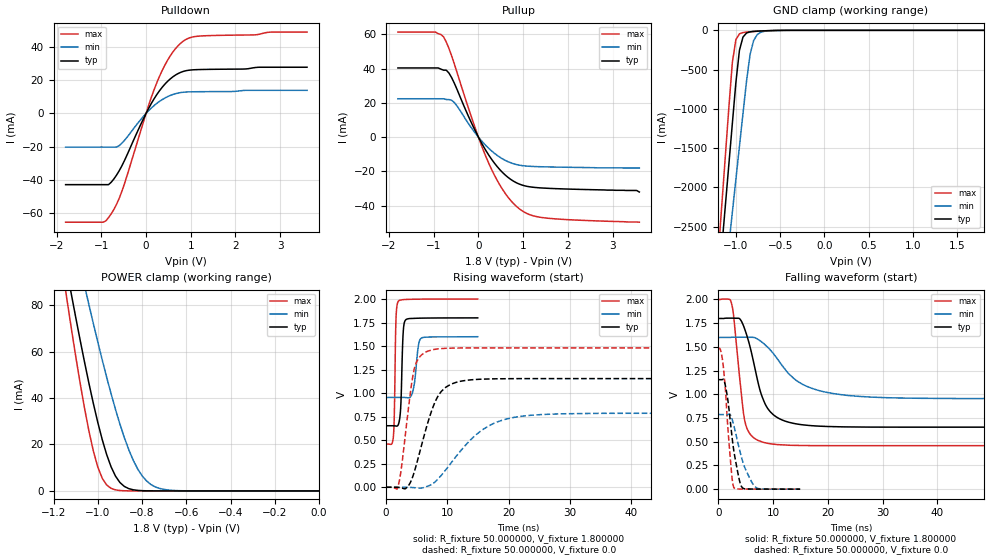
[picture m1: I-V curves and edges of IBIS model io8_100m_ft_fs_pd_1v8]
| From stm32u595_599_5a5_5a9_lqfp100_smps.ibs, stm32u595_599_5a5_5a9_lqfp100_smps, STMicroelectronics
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|   Model io8_100m_ft_fs_pd_1v8
[Model]  io8_100m_ft_fs_pd_1v8
Model_type I/O
Polarity   Non-Inverting
Enable   Active-Low
Vinl =   0.540000V
Vinh =   1.260000V
Vmeas =  0.900000V
Cref =   50.000000pF
Rref =   100.000000M
Vref =   0.0V
C_comp   3.148300pF   3.147400pF   3.196500pF
[Temperature Range]   25.000000   0.140000k   -40.000000
[Pullup Reference]   1.800000V   1.600000V   2.000000V
[Pulldown Reference]   0.0V   0.0V   0.0V
[POWER Clamp Reference]   1.800000V   1.600000V   2.000000V
[GND Clamp Reference]   0.0V   0.0V   0.0V
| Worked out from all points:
|   slope of the pulldown table from 0 to 0.27 V, typ, clamps not added: 21.7 ohm
|   slope of the pullup table from 0 to 0.27 V, typ, clamps not added: 22.6 ohm
|   GND clamp passes 1 mA (typ) near -0.51 V on its own axis
|   POWER clamp passes 1 mA (typ) near -0.86 V on its own axis
|   rising waveform, R_fixture 50.000000, V_fixture 1.800000: 20-80 % time 321ps typ, 625ps min, 233ps max; typ from 0.654 V to 1.8 V
|   rising waveform, R_fixture 50.000000, V_fixture 0.0: 20-80 % time 3.21ns typ, 6.76ns min, 1.69ns max; typ from 0 V to 1.15 V
|   falling waveform, R_fixture 50.000000, V_fixture 1.800000: 20-80 % time 3.22ns typ, 6.74ns min, 1.66ns max; typ from 1.8 V to 0.654 V
|   falling waveform, R_fixture 50.000000, V_fixture 0.0: 20-80 % time 1.6ns typ, 2.38ns min, 1.14ns max; typ from 1.15 V to 0 V
[Pulldown]
|Voltage   I(typ)   I(min)   I(max)
-1.8V     -42.74mA   -20.21mA   -65.25mA
-960mV    -42.74mA   -20.21mA   -65.25mA
-780mV    -41.3mA    -20.21mA   -60.25mA
-660mV    -37mA      -20.2mA    -54.5mA
-540mV    -31.39mA   -17.82mA   -46.65mA
0V        0A         100fA      0A
240mV     11.28mA    6.002mA    18.38mA
480mV     19.17mA    10.02mA    31.83mA
780mV     24.67mA    12.5mA     42.21mA
960mV     25.9mA     12.9mA     45.21mA
1.14V     26.24mA    12.99mA    46.23mA
3.6V      27.67mA    13.81mA    48.75mA
[Pullup]
|Voltage   I(typ)   I(min)   I(max)
-1.8V     40.32mA    22.37mA    61.24mA
-960mV    40.32mA    22.37mA    61.24mA
-780mV    39.04mA    22.37mA    58.49mA
-660mV    37.4mA     21.92mA    51.77mA
-540mV    31.51mA    20.18mA    42.78mA
-120mV    6.338mA    4.065mA    8.965mA
240mV     -10.82mA   -6.752mA   -15.73mA
540mV     -20.62mA   -12.68mA   -30.5mA
900mV     -27.22mA   -16.28mA   -41.49mA
1.14V     -28.94mA   -17mA      -45.14mA
1.5V      -29.77mA   -17.34mA   -47.14mA
3.6V      -32mA      -18mA      -49.6mA
[GND_clamp]
|Voltage   I(typ)   I(min)   I(max)
-1.8V     -9.707A    -9.942A    -9.774A
-1.2V     -3.309A    -4.006A    -2.865A
-1.16V    -2.777A    -3.584A    -2.239A
-1.12V    -2.246A    -3.162A    -1.614A
-1.04V    -1.186A    -2.319A    -408.7mA
-1V       -663.9mA   -1.898A    -117.8mA
-960mV    -254mA     -1.478A    -45.15mA
-920mV    -86.04mA   -1.06A     -28.6mA
-840mV    -19.13mA   -308.9mA   -18.75mA
-800mV    -13.4mA    -130.8mA   -15.33mA
-720mV    -7.959mA   -25.38mA   -9.395mA
1.8V      45.71uA    33.33uA    56.11uA
[POWER_clamp]
|Voltage   I(typ)   I(min)   I(max)
-1.8V     470.8mA    433.7mA    554.6mA
-1.14V    95.25mA    122.7mA    82.82mA
-1.12V    84.97mA    114mA      70.27mA
-1.06V    55.51mA    88.42mA    35.67mA
-1.04V    46.34mA    80.15mA    25.76mA
-1V       29.51mA    64.13mA    10.3mA
-940mV    10.39mA    41.86mA    1.109mA
-900mV    3.624mA    28.77mA    182.8uA
-840mV    490.7uA    13.24mA    11.35uA
-800mV    116.8uA    6.532mA    1.77uA
-740mV    13.2uA     1.723mA    109.3nA
0V        0A         18.72nA    0A
[Ramp]
| variable   typ   min   max
dV/dt_r  0.69258/3.20240n   0.47170/6.75299n   0.88830/1.68877n
dV/dt_f  0.68753/3.21016n   0.38694/6.72881n   0.92451/1.65185n
R_load = 50.000000
[Rising Waveform]
R_fixture= 50.000000
V_fixture= 1.800000
V_fixture_min= 1.600000
V_fixture_max= 2.000000
|time   V(typ)   V(min)   V(max)
0s        653.5mV    954.4mV    458.5mV
1.231ns   653.4mV    954.4mV    543mV
1.652ns   650.5mV    954.4mV    1.789V
2.012ns   663.2mV    954.4mV    1.974V
2.402ns   831mV      954.4mV    1.989V
2.853ns   1.673V     954.2mV    1.994V
3.213ns   1.777V     953.3mV    1.995V
4.414ns   1.794V     1.025V     1.997V
5.766ns   1.797V     1.584V     1.998V
14.95ns   1.799V     1.599V     1.999V
[Rising Waveform]
R_fixture= 50.000000
V_fixture= 0.0
V_fixture_min= 0.0
V_fixture_max= 0.0
|time   V(typ)   V(min)   V(max)
0s        3.637uV    3.108uV    2.586uV
2.002ns   -1.583mV   519.6nV    12.74mV
3.804ns   28.71mV    -635.7uV   905.4mV
5.005ns   248.3mV    -6.201mV   1.331V
7.608ns   839.8mV    36.16mV    1.461V
9.009ns   1.016V     125.5mV    1.473V
11.41ns   1.114V     325.4mV    1.479V
16.42ns   1.15V      638.9mV    1.48V
22.22ns   1.154V     755.2mV    1.48V
99.7ns    1.154V     786.2mV    1.48V
[Falling Waveform]
R_fixture= 50.000000
V_fixture= 1.800000
V_fixture_min= 1.600000
V_fixture_max= 2.000000
|time   V(typ)   V(min)   V(max)
0s        1.799V     1.599V     1.999V
2.202ns   1.803V     1.599V     1.996V
2.603ns   1.803V     1.602V     1.915V
4.404ns   1.751V     1.602V     903.9mV
5.005ns   1.66V      1.601V     682.5mV
8.408ns   918.2mV    1.529V     490.8mV
10.61ns   761.3mV    1.388V     471mV
14.81ns   682.9mV    1.125V     460.7mV
23.42ns   656.4mV    989.3mV    458.5mV
99.7ns    653.5mV    954.4mV    458.5mV
[Falling Waveform]
R_fixture= 50.000000
V_fixture= 0.0
V_fixture_min= 0.0
V_fixture_max= 0.0
|time   V(typ)   V(min)   V(max)
0s        1.154V     786.2mV    1.48V
420.4ps   1.154V     786.2mV    1.467V
930.9ps   1.159V     786.2mV    1.297V
1.562ns   1.014V     786mV      824.2mV
2.342ns   644.5mV    769.5mV    233.4mV
2.613ns   507.6mV    722.5mV    79.43mV
2.853ns   404.1mV    670.8mV    18.33mV
4.234ns   29.51mV    339mV      1.273mV
6.877ns   959.6uV    18.42mV    375.5uV
14.95ns   3.637uV    3.108uV    2.586uV
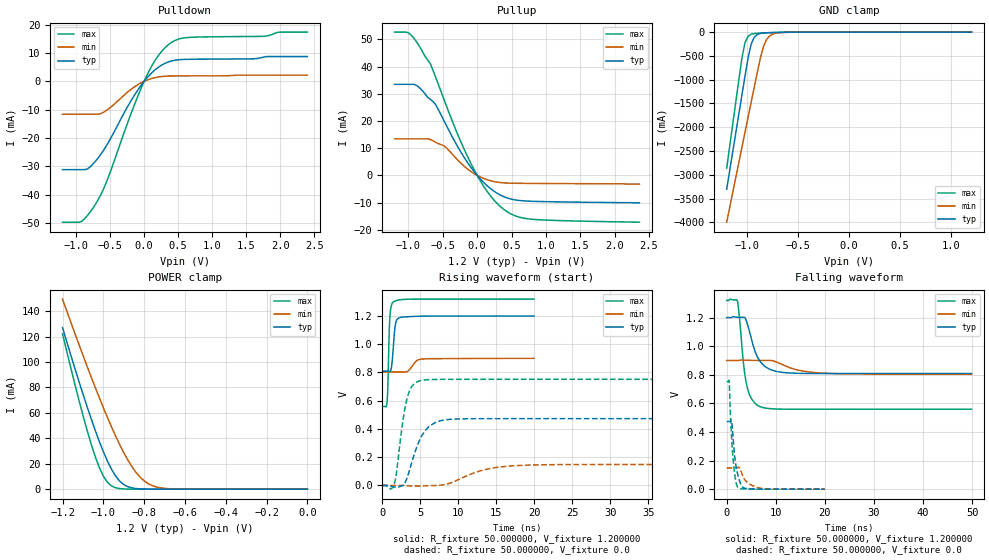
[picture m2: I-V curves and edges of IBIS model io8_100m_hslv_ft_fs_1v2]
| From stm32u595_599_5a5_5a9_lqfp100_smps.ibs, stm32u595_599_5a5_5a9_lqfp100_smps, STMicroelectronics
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|   Model io8_100m_hslv_ft_fs_1v2
[Model]  io8_100m_hslv_ft_fs_1v2
Model_type I/O
Polarity   Non-Inverting
Enable   Active-Low
Vinl =   0.360000V
Vinh =   0.840000V
Vmeas =  0.600000V
Cref =   50.000000pF
Rref =   100.000000M
Vref =   0.0V
C_comp   3.030100pF   2.960800pF   3.078300pF
[Temperature Range]   25.000000   0.140000k   -40.000000
[Pullup Reference]   1.200000V   0.900000V   1.320000V
[Pulldown Reference]   0.0V   0.0V   0.0V
[POWER Clamp Reference]   1.200000V   0.900000V   1.320000V
[GND Clamp Reference]   0.0V   0.0V   0.0V
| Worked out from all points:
|   slope of the pulldown table from 0 to 0.18 V, typ, clamps not added: 40.7 ohm
|   slope of the pullup table from 0 to 0.18 V, typ, clamps not added: 39.5 ohm
|   GND clamp passes 1 mA (typ) near -0.51 V on its own axis
|   POWER clamp passes 1 mA (typ) near -0.86 V on its own axis
|   rising waveform, R_fixture 50.000000, V_fixture 1.200000: 20-80 % time 361ps typ, 839ps min, 238ps max; typ from 0.809 V to 1.2 V
|   rising waveform, R_fixture 50.000000, V_fixture 0.0: 20-80 % time 2ns typ, 4.56ns min, 1.19ns max; typ from 0 V to 0.473 V
|   falling waveform, R_fixture 50.000000, V_fixture 1.200000: 20-80 % time 2.46ns typ, 5.4ns min, 1.5ns max; typ from 1.2 V to 0.809 V
|   falling waveform, R_fixture 50.000000, V_fixture 0.0: 20-80 % time 1.05ns typ, 1.99ns min, 805ps max; typ from 0.473 V to 0 V
[Pulldown]
|Voltage   I(typ)   I(min)   I(max)
-1.2V     -31.16mA   -11.61mA   -49.71mA
-920mV    -31.16mA   -11.61mA   -49.48mA
-840mV    -31mA      -11.61mA   -47.54mA
-720mV    -28.32mA   -11.61mA   -43.58mA
-560mV    -22.95mA   -10.37mA   -35.89mA
-200mV    -7.146mA   -2.964mA   -11.89mA
0V        0A         -900fA     0A
160mV     4.047mA    1.298mA    7.361mA
360mV     6.87mA     1.87mA     13mA
640mV     7.764mA    1.923mA    15.46mA
1.76V     8.564mA    2.187mA    15.9mA
2.4V      8.742mA    2.187mA    17.38mA
[Pullup]
|Voltage   I(typ)   I(min)   I(max)
-1.2V     33.49mA    13.42mA    52.69mA
-960mV    33.49mA    13.42mA    51.6mA
-840mV    32.27mA    13.42mA    47.49mA
-680mV    27.9mA     13.19mA    41.05mA
-600mV    25.88mA    12.07mA    35.88mA
-480mV    20.01mA    10.83mA    27.79mA
-280mV    10.44mA    5.592mA    14.93mA
-80mV     2.58mA     1.232mA    3.849mA
160mV     -4.145mA   -1.713mA   -6.415mA
400mV     -7.963mA   -2.792mA   -12.75mA
800mV     -9.537mA   -2.973mA   -16.14mA
2.36V     -10.1mA    -3.2mA     -17.23mA
[GND_clamp]
|Voltage   I(typ)   I(min)   I(max)
-1.2V     -3.305A    -3.998A    -2.862A
-1.05V    -1.316A    -2.418A    -539.3mA
-1.02V    -921mA     -2.103A    -218.8mA
-990mV    -539.5mA   -1.788A    -87.43mA
-960mV    -252.1mA   -1.474A    -44.36mA
-930mV    -110.5mA   -1.16A     -30.32mA
-870mV    -28.03mA   -549.1mA   -21.09mA
-840mV    -18.43mA   -305.6mA   -18.27mA
-810mV    -13.9mA    -159.7mA   -15.73mA
-780mV    -11.23mA   -82.35mA   -13.37mA
-600mV    -2.976mA   -4.272mA   -3.058mA
1.2V      0A         14.73nA    0A
[POWER_clamp]
|Voltage   I(typ)   I(min)   I(max)
-1.2V     127mA      149.4mA    122.2mA
-1.12V    84.97mA    114mA      70.27mA
-1.06V    55.51mA    88.42mA    35.67mA
-1.02V    37.63mA    72.04mA    17.17mA
-1V       29.51mA    64.13mA    10.3mA
-960mV    15.69mA    48.99mA    2.571mA
-900mV    3.624mA    28.77mA    182.8uA
-840mV    490.7uA    13.24mA    11.35uA
-800mV    116.8uA    6.532mA    1.77uA
-740mV    13.2uA     1.723mA    109.1nA
-620mV    167.3nA    79.35uA    0A
0V        0A         17.84nA    0A
[Ramp]
| variable   typ   min   max
dV/dt_r  0.28373/2.00049n   88.90787m/4.55840n  0.45092/1.18474n
dV/dt_f  0.23462/2.45847n   57.86400m/5.39280n  0.45666/1.49937n
R_load = 50.000000
[Rising Waveform]
R_fixture= 50.000000
V_fixture= 1.200000
V_fixture_min= 0.900000
V_fixture_max= 1.320000
|time   V(typ)   V(min)   V(max)
0s        809mV      803.5mV    559mV
600.6ps   809.7mV    803.6mV    579.9mV
720.7ps   809.6mV    803.6mV    699.4mV
880.9ps   808.1mV    803.6mV    1.047V
1.001ns   806.7mV    803.6mV    1.201V
1.441ns   979.1mV    803.6mV    1.3V
1.762ns   1.151V     803.7mV    1.307V
2.402ns   1.19V      803.7mV    1.315V
5.165ns   1.199V     894.8mV    1.32V
19.94ns   1.2V       900mV      1.32V
[Rising Waveform]
R_fixture= 50.000000
V_fixture= 0.0
V_fixture_min= 0.0
V_fixture_max= 0.0
|time   V(typ)   V(min)   V(max)
0s        -14.66uV   -6.088uV   -48.74uV
1.502ns   -10.15mV   -40.83uV   -1.021mV
1.802ns   -14.88mV   -38.28uV   69.37mV
3.203ns   45.81mV    -1.917mV   606.3mV
3.904ns   168.6mV    -3.804mV   703.2mV
4.905ns   320.9mV    -4.274mV   740.3mV
6.206ns   421.3mV    -1.573mV   749.3mV
9.009ns   468.7mV    18.4mV     751.4mV
17.52ns   472.9mV    140.3mV    751.7mV
49.85ns   473mV      148.3mV    751.7mV
[Falling Waveform]
R_fixture= 50.000000
V_fixture= 1.200000
V_fixture_min= 0.900000
V_fixture_max= 1.320000
|time   V(typ)   V(min)   V(max)
0s        1.2V       900mV      1.32V
2.202ns   1.202V     899.6mV    1.314V
3.403ns   1.202V     902.2mV    885.7mV
4.004ns   1.177V     901.6mV    740.4mV
5.005ns   1.055V     900.9mV    635.7mV
6.707ns   899.1mV    900.7mV    578.6mV
8.709ns   839mV      900.5mV    563.4mV
12.21ns   813.4mV    858.6mV    559.4mV
20.62ns   809mV      809.7mV    559.1mV
49.85ns   809mV      803.5mV    559mV
[Falling Waveform]
R_fixture= 50.000000
V_fixture= 0.0
V_fixture_min= 0.0
V_fixture_max= 0.0
|time   V(typ)   V(min)   V(max)
0s        473mV      148.3mV    751.7mV
480.5ps   473.2mV    148.3mV    757.4mV
1.001ns   479.3mV    148.4mV    358.1mV
1.281ns   369.9mV    148.4mV    219.2mV
1.642ns   225.3mV    148.2mV    103.7mV
1.962ns   149.3mV    148.7mV    36.98mV
2.322ns   93.94mV    152.5mV    10.46mV
3.403ns   10.07mV    83.3mV     1.778mV
6.406ns   756.7uV    10.28mV    120.8uV
19.94ns   -14.66uV   -6.088uV   -48.74uV
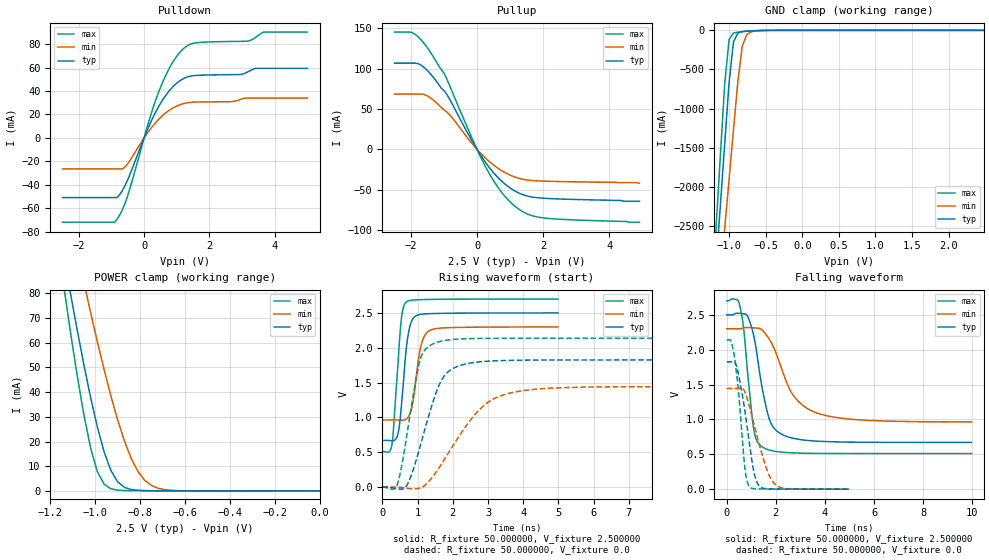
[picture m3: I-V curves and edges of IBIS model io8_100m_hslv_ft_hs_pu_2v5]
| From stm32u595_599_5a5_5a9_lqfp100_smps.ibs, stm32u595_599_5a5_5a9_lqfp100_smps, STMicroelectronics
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|   Model io8_100m_hslv_ft_hs_pu_2v5
[Model]  io8_100m_hslv_ft_hs_pu_2v5
Model_type I/O
Polarity   Non-Inverting
Enable   Active-Low
Vinl =   0.750000V
Vinh =   1.750000V
Vmeas =  1.250000V
Cref =   50.000000pF
Rref =   100.000000M
Vref =   0.0V
C_comp   3.340900pF   3.338500pF   3.380300pF
[Temperature Range]   25.000000   0.140000k   -40.000000
[Pullup Reference]   2.500000V   2.300000V   2.700000V
[Pulldown Reference]   0.0V   0.0V   0.0V
[POWER Clamp Reference]   2.500000V   2.300000V   2.700000V
[GND Clamp Reference]   0.0V   0.0V   0.0V
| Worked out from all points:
|   slope of the pulldown table from 0 to 0.375 V, typ, clamps not added: 16.1 ohm
|   slope of the pullup table from 0 to 0.375 V, typ, clamps not added: 16.6 ohm
|   GND clamp passes 1 mA (typ) near -0.50 V on its own axis
|   POWER clamp passes 1 mA (typ) near -0.85 V on its own axis
|   rising waveform, R_fixture 50.000000, V_fixture 2.500000: 20-80 % time 199ps typ, 229ps min, 179ps max; typ from 0.671 V to 2.5 V
|   rising waveform, R_fixture 50.000000, V_fixture 0.0: 20-80 % time 660ps typ, 1.22ns min, 423ps max; typ from 0.001 V to 1.83 V
|   falling waveform, R_fixture 50.000000, V_fixture 2.500000: 20-80 % time 569ps typ, 1.09ns min, 362ps max; typ from 2.5 V to 0.671 V
|   falling waveform, R_fixture 50.000000, V_fixture 0.0: 20-80 % time 468ps typ, 674ps min, 321ps max; typ from 1.83 V to 0.001 V
[Pulldown]
|Voltage   I(typ)   I(min)   I(max)
-2.5V     -51mA      -26.45mA   -72.04mA
-900mV    -51mA      -26.45mA   -72.04mA
-820mV    -50.89mA   -26.45mA   -69.09mA
-500mV    -35.59mA   -21.93mA   -49.09mA
140mV     9.488mA    5.639mA    13.76mA
460mV     27.5mA     16.24mA    40.22mA
860mV     43.07mA    25.18mA    63.88mA
1.26V     51.38mA    29.65mA    77.49mA
1.66V     53.45mA    30.63mA    81.42mA
3.18V     56.44mA    33.99mA    82.68mA
3.66V     59.4mA     33.99mA    90.38mA
5V        59.4mA     33.99mA    90.38mA
[Pullup]
|Voltage   I(typ)   I(min)   I(max)
-2.5V     106.7mA    68.57mA    145.2mA
-1.96V    106.7mA    68.57mA    144.4mA
-1.72V    104.8mA    68.57mA    136.6mA
-1.48V    96.52mA    65.55mA    124.2mA
-1V       72.66mA    48.88mA    94.2mA
-120mV    8.307mA    5.657mA    10.97mA
280mV     -17.4mA    -11.68mA   -23.32mA
680mV     -36.72mA   -24.56mA   -49.54mA
1.16V     -51.75mA   -34.32mA   -70.71mA
1.56V     -58mA      -38.01mA   -80.45mA
1.96V     -60.18mA   -39.11mA   -84.44mA
4.92V     -64mA      -42mA      -90mA
[GND_clamp]
|Voltage   I(typ)   I(min)   I(max)
-2.5V     -9.446A    -9.524A    -9.146A
-1.18V    -3.045A    -3.8A      -2.552A
-1.12V    -2.248A    -3.166A    -1.614A
-1.06V    -1.452A    -2.533A    -685.3mA
-1V       -665mA     -1.901A    -117.9mA
-940mV    -148mA     -1.272A    -34.32mA
-880mV    -35.13mA   -651.5mA   -22.79mA
-820mV    -16mA      -203.9mA   -17.07mA
-760mV    -10.46mA   -56.88mA   -12.26mA
-700mV    -7.068mA   -18.52mA   -8.146mA
-400mV    -103.3uA   -375.9uA   -42.12uA
2.48V     0A         14.84nA    0A
[POWER_clamp]
|Voltage   I(typ)   I(min)   I(max)
-2.49V    881.1mA    773.1mA    1.07A
-1.14V    95.32mA    122.8mA    82.93mA
-1.11V    79.97mA    109.7mA    64.26mA
-1.05V    50.95mA    84.3mA     30.69mA
-1.02V    37.7mA     72.08mA    17.29mA
-990mV    25.79mA    60.29mA    7.738mA
-930mV    8.312mA    38.47mA    853.6uA
-900mV    3.712mA    28.81mA    314.2uA
-840mV    566.7uA    13.29mA    124.4uA
-780mV    119.5uA    4.365mA    94.68uA
-660mV    39.4uA     251.7uA    58.31uA
0V        0A         18.89nA    0A
[Ramp]
| variable   typ   min   max
dV/dt_r  1.09488/0.65885n   0.86563/1.21820n   1.28167/0.42251n
dV/dt_f  1.09763/0.56761n   0.80096/1.08475n   1.31314/0.36128n
R_load = 50.000000
[Rising Waveform]
R_fixture= 50.000000
V_fixture= 2.500000
V_fixture_min= 2.300000
V_fixture_max= 2.700000
|time   V(typ)   V(min)   V(max)
0s        670.7mV    964mV      511.2mV
270.3ps   665.2mV    964.4mV    607.5mV
310.3ps   665.8mV    964.4mV    795.3mV
450.5ps   781.4mV    963.8mV    1.821V
550.6ps   1.226V     960.8mV    2.46V
680.7ps   1.997V     977.3mV    2.657V
860.9ps   2.412V     1.202V     2.684V
1.101ns   2.481V     2.035V     2.691V
1.341ns   2.489V     2.247V     2.694V
4.985ns   2.5V       2.3V       2.699V
[Rising Waveform]
R_fixture= 50.000000
V_fixture= 0.0
V_fixture_min= 0.0
V_fixture_max= 0.0
|time   V(typ)   V(min)   V(max)
0s        547.2uV    719.7uV    325.8uV
400.4ps   -23.35mV   606.1uV    5.571mV
680.7ps   13.74mV    -14.48mV   697.2mV
1.081ns   601.9mV    -12.24mV   1.842V
1.461ns   1.262V     171.4mV    2.061V
1.702ns   1.554V     349.1mV    2.098V
2.022ns   1.708V     609.2mV    2.12V
2.763ns   1.799V     1.115V     2.134V
3.423ns   1.817V     1.322V     2.136V
9.97ns    1.826V     1.444V     2.136V
[Falling Waveform]
R_fixture= 50.000000
V_fixture= 2.500000
V_fixture_min= 2.300000
V_fixture_max= 2.700000
|time   V(typ)   V(min)   V(max)
0s        2.5V       2.3V       2.699V
520.5ps   2.521V     2.299V     2.648V
700.7ps   2.514V     2.314V     2.272V
1.101ns   2.201V     2.313V     863.2mV
1.461ns   1.418V     2.275V     603mV
1.722ns   1.02V      2.158V     562.8mV
1.962ns   861.9mV    1.993V     543.7mV
2.623ns   737.2mV    1.395V     521.9mV
3.443ns   694.2mV    1.125V     514.2mV
9.97ns    670.7mV    964mV      511.2mV
[Falling Waveform]
R_fixture= 50.000000
V_fixture= 0.0
V_fixture_min= 0.0
V_fixture_max= 0.0
|time   V(typ)   V(min)   V(max)
0s        1.826V     1.444V     2.136V
300.3ps   1.831V     1.444V     1.932V
470.5ps   1.666V     1.445V     1.444V
740.7ps   1.125V     1.395V     301.8mV
930.9ps   646.6mV    1.183V     37.17mV
1.121ns   224.5mV    919.3mV    6.992mV
1.281ns   67.99mV    700.4mV    4.455mV
1.662ns   6.26mV     253.6mV    2.589mV
2.002ns   3.736mV    62.31mV    1.688mV
4.985ns   547.2uV    719.7uV    325.8uV
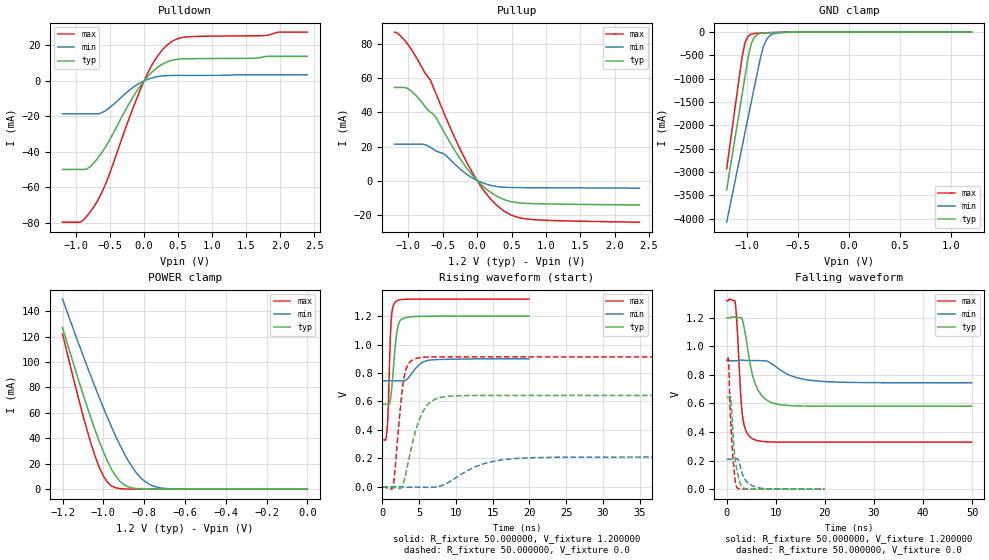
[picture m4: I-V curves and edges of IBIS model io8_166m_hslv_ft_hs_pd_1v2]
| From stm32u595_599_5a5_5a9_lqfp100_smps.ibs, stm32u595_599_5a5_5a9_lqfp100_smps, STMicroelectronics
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|   Model io8_166m_hslv_ft_hs_pd_1v2
[Model]  io8_166m_hslv_ft_hs_pd_1v2
Model_type I/O
Polarity   Non-Inverting
Enable   Active-Low
Vinl =   0.360000V
Vinh =   0.840000V
Vmeas =  0.600000V
Cref =   50.000000pF
Rref =   100.000000M
Vref =   0.0V
C_comp   3.151700pF   3.087200pF   3.197900pF
[Temperature Range]   25.000000   0.140000k   -40.000000
[Pullup Reference]   1.200000V   0.900000V   1.320000V
[Pulldown Reference]   0.0V   0.0V   0.0V
[POWER Clamp Reference]   1.200000V   0.900000V   1.320000V
[GND Clamp Reference]   0.0V   0.0V   0.0V
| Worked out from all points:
|   slope of the pulldown table from 0 to 0.18 V, typ, clamps not added: 25.4 ohm
|   slope of the pullup table from 0 to 0.18 V, typ, clamps not added: 27.8 ohm
|   GND clamp passes 1 mA (typ) near -0.51 V on its own axis
|   POWER clamp passes 1 mA (typ) near -0.86 V on its own axis
|   rising waveform, R_fixture 50.000000, V_fixture 1.200000: 20-80 % time 652ps typ, 1.59ns min, 370ps max; typ from 0.581 V to 1.2 V
|   rising waveform, R_fixture 50.000000, V_fixture 0.0: 20-80 % time 2.04ns typ, 4.81ns min, 1.01ns max; typ from 0 V to 0.642 V
|   falling waveform, R_fixture 50.000000, V_fixture 1.200000: 20-80 % time 2.38ns typ, 5.33ns min, 1.03ns max; typ from 1.2 V to 0.581 V
|   falling waveform, R_fixture 50.000000, V_fixture 0.0: 20-80 % time 1.03ns typ, 1.72ns min, 823ps max; typ from 0.642 V to 0 V
[Pulldown]
|Voltage   I(typ)   I(min)   I(max)
-1.2V     -49.86mA   -18.57mA   -79.56mA
-920mV    -49.86mA   -18.57mA   -79.19mA
-840mV    -49.6mA    -18.57mA   -76.08mA
-720mV    -45.32mA   -18.57mA   -69.74mA
-560mV    -36.71mA   -16.58mA   -57.44mA
-200mV    -11.43mA   -4.74mA    -19.03mA
0V        -10fA      -600fA     0A
160mV     6.477mA    2.075mA    11.78mA
360mV     10.99mA    2.99mA     20.81mA
480mV     12.07mA    3.054mA    23.53mA
640mV     12.43mA    3.075mA    24.76mA
2.4V      13.79mA    3.434mA    27.44mA
[Pullup]
|Voltage   I(typ)   I(min)   I(max)
-1.2V     54.72mA    21.36mA    87.24mA
-1.04V    54.62mA    21.36mA    81.75mA
-880mV    49.53mA    21.36mA    72.04mA
-680mV    40.23mA    19.55mA    59.03mA
-600mV    37.19mA    17.44mA    51.24mA
-480mV    28.49mA    15.59mA    39.53mA
-80mV     3.667mA    1.75mA     5.47mA
120mV     -4.592mA   -1.936mA   -7.077mA
360mV     -10.68mA   -3.85mA    -16.99mA
560mV     -12.87mA   -4.135mA   -21.24mA
760mV     -13.48mA   -4.204mA   -22.78mA
2.36V     -14.3mA    -4.5mA     -24.47mA
[GND_clamp]
|Voltage   I(typ)   I(min)   I(max)
-1.2V     -3.379A    -4.076A    -2.932A
-1.05V    -1.35A     -2.47A     -550.7mA
-1.02V    -947.8mA   -2.15A     -221.5mA
-990mV    -552.4mA   -1.829A    -88.45mA
-960mV    -255.3mA   -1.51A     -44.89mA
-930mV    -111.8mA   -1.191A    -30.7mA
-870mV    -28.37mA   -564.6mA   -21.36mA
-840mV    -18.66mA   -309.5mA   -18.51mA
-810mV    -14.08mA   -161.6mA   -15.94mA
-780mV    -11.38mA   -83.33mA   -13.55mA
-600mV    -3.02mA    -4.329mA   -3.104mA
1.2V      30.28uA    18.17uA    37.27uA
[POWER_clamp]
|Voltage   I(typ)   I(min)   I(max)
-1.2V     127mA      149.4mA    122.2mA
-1.12V    84.97mA    114mA      70.27mA
-1.06V    55.51mA    88.42mA    35.67mA
-1.02V    37.63mA    72.04mA    17.17mA
-1V       29.51mA    64.13mA    10.3mA
-960mV    15.69mA    48.99mA    2.571mA
-900mV    3.624mA    28.77mA    182.8uA
-840mV    490.7uA    13.24mA    11.35uA
-800mV    116.8uA    6.532mA    1.77uA
-740mV    13.2uA     1.723mA    109.1nA
-620mV    167.4nA    79.36uA    0A
0V        0A         17.87nA    0A
[Ramp]
| variable   typ   min   max
dV/dt_r  0.38525/2.03988n   0.12539/4.80825n   0.54788/1.00459n
dV/dt_f  0.37096/2.37294n   92.62800m/5.32307n  0.59420/1.02355n
R_load = 50.000000
[Rising Waveform]
R_fixture= 50.000000
V_fixture= 1.200000
V_fixture_min= 0.900000
V_fixture_max= 1.320000
|time   V(typ)   V(min)   V(max)
0s        581.3mV    745.1mV    329.3mV
600.6ps   581.6mV    745.1mV    379.8mV
800.8ps   579.7mV    745.1mV    552.3mV
1.041ns   595.2mV    745.2mV    981.4mV
1.201ns   653.9mV    745.2mV    1.167V
1.842ns   1.034V     745.3mV    1.303V
2.362ns   1.164V     745.2mV    1.314V
3.524ns   1.193V     765.3mV    1.319V
6.527ns   1.199V     891.5mV    1.319V
19.94ns   1.2V       899.5mV    1.319V
[Rising Waveform]
R_fixture= 50.000000
V_fixture= 0.0
V_fixture_min= 0.0
V_fixture_max= 0.0
|time   V(typ)   V(min)   V(max)
0s        -6.994uV   -242.7nV   -35.93uV
1.401ns   -6.348mV   -19.82uV   -8.301mV
2.903ns   33.75mV    -510.7uV   754.5mV
3.504ns   168.4mV    -3.226mV   858.9mV
4.605ns   406.8mV    -2.361mV   902.8mV
6.206ns   579.8mV    -4.031mV   912.1mV
8.909ns   635.8mV    28.58mV    913.1mV
13.41ns   641.9mV    155.5mV    913.2mV
18.32ns   642.1mV    199.7mV    913.2mV
49.85ns   642.2mV    209.1mV    913.3mV
[Falling Waveform]
R_fixture= 50.000000
V_fixture= 1.200000
V_fixture_min= 0.900000
V_fixture_max= 1.320000
|time   V(typ)   V(min)   V(max)
0s        1.2V       899.5mV    1.319V
1.702ns   1.204V     899.4mV    1.313V
2.002ns   1.202V     899.2mV    1.205V
3.203ns   1.186V     902.7mV    519.2mV
3.904ns   1.064V     901.4mV    411mV
5.305ns   791mV      900.2mV    352.6mV
7.508ns   641.5mV    899.5mV    333.5mV
11.01ns   590.8mV    832.5mV    329.6mV
20.02ns   581.4mV    753.2mV    329.3mV
49.85ns   581.3mV    745.1mV    329.3mV
[Falling Waveform]
R_fixture= 50.000000
V_fixture= 0.0
V_fixture_min= 0.0
V_fixture_max= 0.0
|time   V(typ)   V(min)   V(max)
0s        642.2mV    209.1mV    913.3mV
400.4ps   642.2mV    209.1mV    884.7mV
680.7ps   646.6mV    209.2mV    573.1mV
840.8ps   641.5mV    209.2mV    463.2mV
1.161ns   456.2mV    209.2mV    273.1mV
1.481ns   297.3mV    209mV      141.7mV
2.082ns   132.2mV    213.1mV    10.61mV
3.203ns   12.39mV    104.9mV    1.609mV
5.646ns   1.029mV    18.57mV    139.8uV
19.94ns   -6.994uV   -242.7nV   -35.93uV
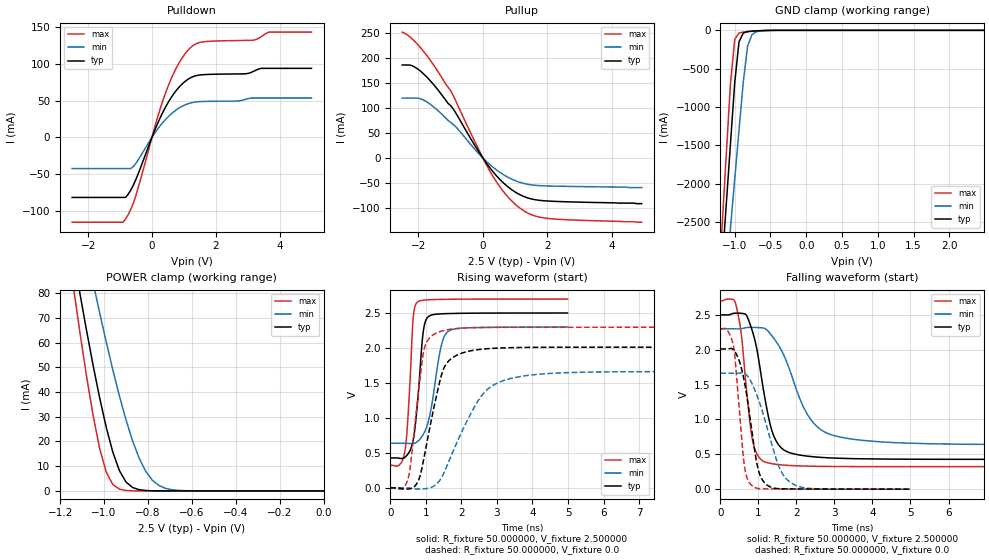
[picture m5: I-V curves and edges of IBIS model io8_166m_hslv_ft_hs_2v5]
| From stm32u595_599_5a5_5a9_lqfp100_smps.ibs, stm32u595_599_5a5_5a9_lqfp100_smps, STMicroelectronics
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|   Model io8_166m_hslv_ft_hs_2v5
[Model]  io8_166m_hslv_ft_hs_2v5
Model_type I/O
Polarity   Non-Inverting
Enable   Active-Low
Vinl =   0.750000V
Vinh =   1.750000V
Vmeas =  1.250000V
Cref =   50.000000pF
Rref =   100.000000M
Vref =   0.0V
C_comp   3.458600pF   3.458000pF   3.495600pF
[Temperature Range]   25.000000   0.140000k   -40.000000
[Pullup Reference]   2.500000V   2.300000V   2.700000V
[Pulldown Reference]   0.0V   0.0V   0.0V
[POWER Clamp Reference]   2.500000V   2.300000V   2.700000V
[GND Clamp Reference]   0.0V   0.0V   0.0V
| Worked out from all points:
|   slope of the pulldown table from 0 to 0.375 V, typ, clamps not added: 10.1 ohm
|   slope of the pullup table from 0 to 0.375 V, typ, clamps not added: 11.7 ohm
|   GND clamp passes 1 mA (typ) near -0.50 V on its own axis
|   POWER clamp passes 1 mA (typ) near -0.86 V on its own axis
|   rising waveform, R_fixture 50.000000, V_fixture 2.500000: 20-80 % time 205ps typ, 326ps min, 149ps max; typ from 0.428 V to 2.5 V
|   rising waveform, R_fixture 50.000000, V_fixture 0.0: 20-80 % time 500ps typ, 981ps min, 304ps max; typ from 0 V to 2.01 V
|   falling waveform, R_fixture 50.000000, V_fixture 2.500000: 20-80 % time 425ps typ, 790ps min, 267ps max; typ from 2.5 V to 0.428 V
|   falling waveform, R_fixture 50.000000, V_fixture 0.0: 20-80 % time 341ps typ, 562ps min, 213ps max; typ from 2.01 V to 0 V
[Pulldown]
|Voltage   I(typ)   I(min)   I(max)
-2.5V     -81.62mA   -42.31mA   -115.3mA
-900mV    -81.62mA   -42.31mA   -115.3mA
-820mV    -81.43mA   -42.31mA   -110.6mA
-500mV    -56.95mA   -35.08mA   -78.57mA
140mV     15.18mA    9.02mA     22.02mA
460mV     44mA       25.98mA    64.38mA
860mV     68.91mA    40.27mA    102.2mA
1.26V     82.21mA    47.42mA    124mA
1.66V     85.54mA    49mA       130.3mA
3.18V     89.84mA    53.64mA    132.3mA
3.66V     94.01mA    53.64mA    143.3mA
5V        94.01mA    53.64mA    143.3mA
[Pullup]
|Voltage   I(typ)   I(min)   I(max)
-2.5V     185.5mA    119.5mA    251.1mA
-2.12V    181.7mA    119.5mA    233.1mA
-1.88V    170.2mA    116.8mA    215.9mA
-1.64V    154.6mA    107.5mA    195.7mA
-1V       104.5mA    70.68mA    134.6mA
-120mV    11.81mA    8.046mA    15.6mA
280mV     -24.75mA   -16.62mA   -33.17mA
680mV     -52.22mA   -34.93mA   -70.46mA
1.08V     -70.88mA   -47.09mA   -96.6mA
1.48V     -81.29mA   -53.4mA    -112.4mA
1.96V     -85.56mA   -55.61mA   -120.1mA
4.92V     -91mA      -59mA      -128mA
[GND_clamp]
|Voltage   I(typ)   I(min)   I(max)
-2.5V     -9.641A    -9.693A    -9.352A
-1.18V    -3.114A    -3.874A    -2.614A
-1.12V    -2.301A    -3.23A     -1.656A
-1.06V    -1.489A    -2.587A    -706.2mA
-1V       -685.8mA   -1.945A    -119.3mA
-940mV    -149.7mA   -1.304A    -34.73mA
-880mV    -35.54mA   -672.6mA   -23.06mA
-820mV    -16.2mA    -206.4mA   -17.27mA
-760mV    -10.58mA   -57.55mA   -12.41mA
-700mV    -7.152mA   -18.74mA   -8.24mA
-400mV    -103.3uA   -378.6uA   -41.75uA
2.48V     0A         13.22nA    0A
[POWER_clamp]
|Voltage   I(typ)   I(min)   I(max)
-2.49V    881mA      773.1mA    1.07A
-1.14V    95.25mA    122.7mA    82.82mA
-1.11V    79.9mA     109.7mA    64.14mA
-1.05V    50.87mA    84.26mA    30.57mA
-1.02V    37.63mA    72.04mA    17.17mA
-990mV    25.71mA    60.25mA    7.621mA
-930mV    8.217mA    38.43mA    713.9uA
-900mV    3.624mA    28.77mA    182.8uA
-840mV    490.7uA    13.24mA    11.35uA
-780mV    56.55uA    4.324mA    699nA
-660mV    716.7nA    226uA      9.784nA
0V        0A         19.53nA    0A
[Ramp]
| variable   typ   min   max
dV/dt_r  1.20666/0.49977n   0.99768/0.97942n   1.37784/0.30312n
dV/dt_f  1.24343/0.42424n   0.99712/0.78878n   1.42636/0.26622n
R_load = 50.000000
[Rising Waveform]
R_fixture= 50.000000
V_fixture= 2.500000
V_fixture_min= 2.300000
V_fixture_max= 2.700000
|time   V(typ)   V(min)   V(max)
0s        427.6mV    637.5mV    322.7mV
410.4ps   435.6mV    637.7mV    521.5mV
500.5ps   486.5mV    636.2mV    1.036V
640.6ps   674.4mV    632.8mV    2.403V
750.8ps   1.135V     655.3mV    2.65V
900.9ps   2.111V     741.6mV    2.681V
981ps     2.368V     816.9mV    2.685V
1.431ns   2.488V     2.024V     2.694V
1.642ns   2.492V     2.241V     2.696V
4.985ns   2.5V       2.3V       2.699V
[Rising Waveform]
R_fixture= 50.000000
V_fixture= 0.0
V_fixture_min= 0.0
V_fixture_max= 0.0
|time   V(typ)   V(min)   V(max)
0s        -52.67uV   -22.14uV   -41.78uV
500.5ps   -16.69mV   -722.5uV   131.4mV
800.8ps   115.6mV    -17.4mV    1.407V
981ps     516.1mV    -12.62mV   2.035V
1.321ns   1.366V     64.76mV    2.219V
1.502ns   1.705V     205.7mV    2.25V
1.742ns   1.857V     492.4mV    2.271V
2.543ns   1.98V      1.299V     2.292V
3.183ns   2.001V     1.534V     2.295V
9.97ns    2.011V     1.663V     2.296V
[Falling Waveform]
R_fixture= 50.000000
V_fixture= 2.500000
V_fixture_min= 2.300000
V_fixture_max= 2.700000
|time   V(typ)   V(min)   V(max)
0s        2.5V       2.3V       2.699V
400.4ps   2.524V     2.3V       2.662V
540.5ps   2.522V     2.301V     2.259V
840.8ps   2.268V     2.321V     713mV
1.161ns   1.332V     2.306V     392.7mV
1.361ns   827.8mV    2.195V     365.2mV
1.622ns   582.5mV    1.975V     347.6mV
2.262ns   475.1mV    1.097V     331mV
2.843ns   449.7mV    794.8mV    326.2mV
9.97ns    427.6mV    637.5mV    322.7mV
[Falling Waveform]
R_fixture= 50.000000
V_fixture= 0.0
V_fixture_min= 0.0
V_fixture_max= 0.0
|time   V(typ)   V(min)   V(max)
0s        2.011V     1.663V     2.296V
180.2ps   2.011V     1.663V     2.279V
340.3ps   2V         1.663V     2.061V
620.6ps   1.569V     1.664V     380.2mV
820.8ps   862.3mV    1.527V     55.92mV
971ps     336.6mV    1.329V     12.29mV
1.111ns   126.8mV    1.106V     5.514mV
1.542ns   6.842mV    319.5mV    2.378mV
1.872ns   3.604mV    86.94mV    1.424mV
4.985ns   -52.67uV   -22.14uV   -41.78uV
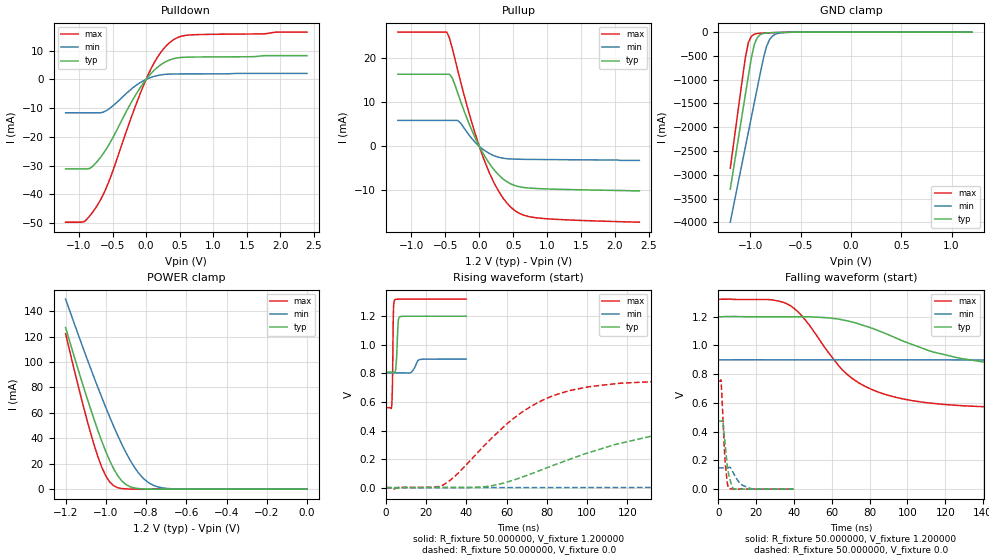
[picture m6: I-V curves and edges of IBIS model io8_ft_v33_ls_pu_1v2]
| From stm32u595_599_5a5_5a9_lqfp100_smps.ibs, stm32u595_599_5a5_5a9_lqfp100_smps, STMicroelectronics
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|   Model io8_ft_v33_ls_pu_1v2
[Model]  io8_ft_v33_ls_pu_1v2
Model_type I/O
Polarity   Non-Inverting
Enable   Active-Low
Vinl =   0.360000V
Vinh =   0.840000V
Vmeas =  0.600000V
Cref =   50.000000pF
Rref =   100.000000M
Vref =   0.0V
C_comp   2.887200pF   2.816900pF   2.935200pF
[Temperature Range]   25.000000   0.140000k   -40.000000
[Pullup Reference]   1.200000V   0.900000V   1.320000V
[Pulldown Reference]   0.0V   0.0V   0.0V
[POWER Clamp Reference]   1.200000V   0.900000V   1.320000V
[GND Clamp Reference]   0.0V   0.0V   0.0V
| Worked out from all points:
|   slope of the pulldown table from 0 to 0.18 V, typ, clamps not added: 40.7 ohm
|   slope of the pullup table from 0 to 0.18 V, typ, clamps not added: 39.5 ohm
|   GND clamp passes 1 mA (typ) near -0.51 V on its own axis
|   POWER clamp passes 1 mA (typ) near -0.86 V on its own axis
|   rising waveform, R_fixture 50.000000, V_fixture 1.200000: 20-80 % time 751ps typ, 2.07ns min, 413ps max; typ from 0.809 V to 1.2 V
|   rising waveform, R_fixture 50.000000, V_fixture 0.0: 20-80 % time 67.6ns typ, 169ns min, 37.1ns max; typ from 0.001 V to 0.474 V
|   falling waveform, R_fixture 50.000000, V_fixture 1.200000: 20-80 % time 58.1ns typ, 149ns min, 31.6ns max; typ from 1.2 V to 0.809 V
|   falling waveform, R_fixture 50.000000, V_fixture 0.0: 20-80 % time 2.49ns typ, 4.76ns min, 1.84ns max; typ from 0.474 V to 0.001 V
[Pulldown]
|Voltage   I(typ)   I(min)   I(max)
-1.2V     -31.16mA   -11.61mA   -49.71mA
-920mV    -31.16mA   -11.61mA   -49.49mA
-840mV    -31mA      -11.61mA   -47.54mA
-720mV    -28.32mA   -11.61mA   -43.58mA
-560mV    -22.95mA   -10.37mA   -35.89mA
-200mV    -7.146mA   -2.964mA   -11.89mA
0V        0A         0A         0A
160mV     4.047mA    1.298mA    7.361mA
360mV     6.869mA    1.87mA     13mA
480mV     7.543mA    1.91mA     14.69mA
640mV     7.765mA    1.923mA    15.46mA
2.4V      8.292mA    2.092mA    16.49mA
[Pullup]
|Voltage   I(typ)   I(min)   I(max)
-1.2V     16.38mA    5.9mA      25.96mA
-480mV    16.38mA    5.9mA      25.96mA
-440mV    16.38mA    5.9mA      24.63mA
-400mV    15.57mA    5.9mA      22.35mA
-320mV    12.21mA    5.9mA      17.37mA
-120mV    3.997mA    1.962mA    5.905mA
80mV      -2.237mA   -962.6uA   -3.434mA
280mV     -6.404mA   -2.453mA   -10.06mA
520mV     -8.88mA    -2.9mA     -14.54mA
680mV     -9.389mA   -2.951mA   -15.76mA
920mV     -9.627mA   -2.991mA   -16.35mA
2.36V     -10.1mA    -3.2mA     -17.23mA
[GND_clamp]
|Voltage   I(typ)   I(min)   I(max)
-1.2V     -3.305A    -3.998A    -2.862A
-1.05V    -1.316A    -2.418A    -539.3mA
-1.02V    -921mA     -2.103A    -218.8mA
-990mV    -539.5mA   -1.788A    -87.43mA
-960mV    -252.1mA   -1.474A    -44.36mA
-930mV    -110.5mA   -1.16A     -30.32mA
-870mV    -28.03mA   -549.1mA   -21.09mA
-840mV    -18.43mA   -305.6mA   -18.27mA
-810mV    -13.9mA    -159.7mA   -15.73mA
-780mV    -11.23mA   -82.35mA   -13.37mA
-600mV    -2.976mA   -4.272mA   -3.058mA
1.2V      0A         14.74nA    0A
[POWER_clamp]
|Voltage   I(typ)   I(min)   I(max)
-1.2V     127mA      149.4mA    122.2mA
-1.12V    84.98mA    114mA      70.29mA
-1.06V    55.52mA    88.42mA    35.69mA
-1.02V    37.64mA    72.04mA    17.19mA
-1V       29.52mA    64.13mA    10.33mA
-960mV    15.7mA     48.99mA    2.597mA
-900mV    3.636mA    28.77mA    209uA
-840mV    503.6uA    13.24mA    43.76uA
-800mV    129.7uA    6.535mA    43.76uA
-740mV    27.38uA    1.727mA    43.76uA
-620mV    25.25uA    82.57uA    35.67uA
0V        0A         17.33nA    0A
[Ramp]
| variable   typ   min   max
dV/dt_r  0.28389/67.54077n   88.97385m/0.16851u  0.45093/37.05634n
dV/dt_f  0.23434/58.02290n   57.81600m/0.14871u  0.45608/31.58209n
R_load = 50.000000
[Rising Waveform]
R_fixture= 50.000000
V_fixture= 1.200000
V_fixture_min= 0.900000
V_fixture_max= 1.320000
|time   V(typ)   V(min)   V(max)
0s        809.5mV    803.6mV    559.9mV
2.883ns   809.6mV    803.6mV    569.2mV
3.283ns   809.5mV    803.6mV    731.8mV
3.764ns   808mV      803.6mV    1.238V
4.324ns   804.9mV    803.6mV    1.313V
5.125ns   868.6mV    803.6mV    1.319V
6.166ns   1.164V     803.6mV    1.319V
6.807ns   1.195V     803.6mV    1.32V
16.98ns   1.2V       897.4mV    1.32V
39.88ns   1.2V       900mV      1.32V
[Rising Waveform]
R_fixture= 50.000000
V_fixture= 0.0
V_fixture_min= 0.0
V_fixture_max= 0.0
|time   V(typ)   V(min)   V(max)
0s        591.7uV    600.2uV    545.2uV
28.03ns   1.425mV    899.1uV    15.95mV
52.05ns   12.22mV    905.1uV    339.7mV
72.07ns   96.51mV    929.1uV    568.3mV
92.09ns   202.4mV    998.6uV    681.9mV
116.1ns   309.4mV    1.314mV    730.7mV
164.2ns   423.7mV    6.645mV    749.9mV
242.2ns   467.6mV    48.06mV    752.3mV
452.5ns   473.7mV    135.6mV    752.1mV
997ns     473.8mV    149mV      752.2mV
[Falling Waveform]
R_fixture= 50.000000
V_fixture= 1.200000
V_fixture_min= 0.900000
V_fixture_max= 1.320000
|time   V(typ)   V(min)   V(max)
0s        1.2V       900mV      1.32V
36.04ns   1.2V       900mV      1.291V
44.04ns   1.2V       900mV      1.208V
66.07ns   1.177V     900mV      823.8mV
76.08ns   1.142V     900mV      726.5mV
98.1ns    1.028V     900mV      627.2mV
130.1ns   905.9mV    899.5mV    580.3mV
256.3ns   815.1mV    860.5mV    560mV
416.4ns   809.6mV    815.6mV    559.9mV
997ns     809.5mV    803.6mV    559.9mV
[Falling Waveform]
R_fixture= 50.000000
V_fixture= 0.0
V_fixture_min= 0.0
V_fixture_max= 0.0
|time   V(typ)   V(min)   V(max)
0s        473.8mV    149mV      752.2mV
1.522ns   473.4mV    149mV      750.9mV
2.482ns   474.2mV    149mV      504.5mV
3.604ns   321.7mV    149mV      204.3mV
4.885ns   157.4mV    148.9mV    39.61mV
5.606ns   100.1mV    151.1mV    5.603mV
8.248ns   3.158mV    107.7mV    1.477mV
11.61ns   943.8uV    40.13mV    1.102mV
16.02ns   605.7uV    9.627mV    1.087mV
39.88ns   591.7uV    600.2uV    545.2uV
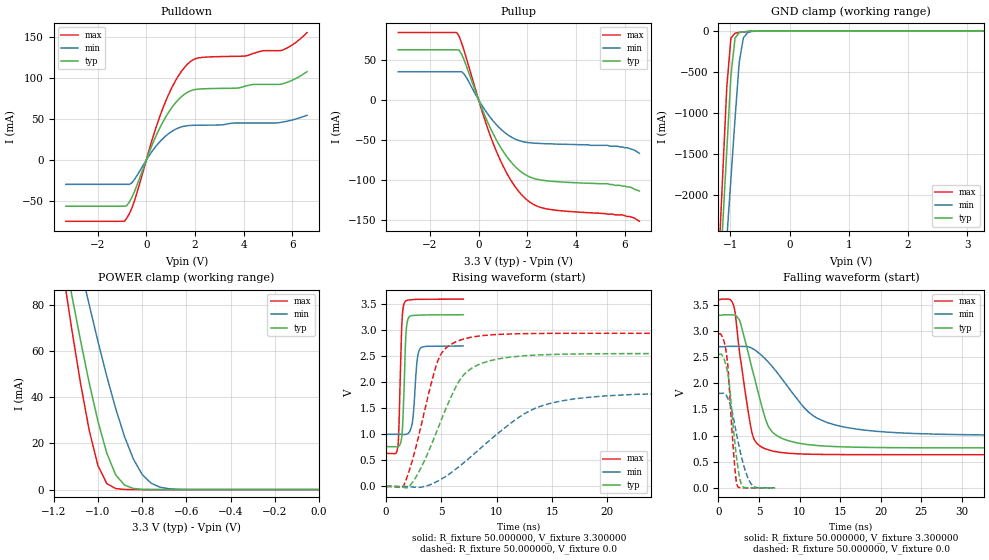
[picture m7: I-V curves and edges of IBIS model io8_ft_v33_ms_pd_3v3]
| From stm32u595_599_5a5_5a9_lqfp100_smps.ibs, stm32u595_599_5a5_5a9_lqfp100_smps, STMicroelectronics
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|   Model io8_ft_v33_ms_pd_3v3
[Model]  io8_ft_v33_ms_pd_3v3
Model_type I/O
Polarity   Non-Inverting
Enable   Active-Low
Vinl =   0.990000V
Vinh =   2.310000V
Vmeas =  1.650000V
Cref =   50.000000pF
Rref =   100.000000M
Vref =   0.0V
C_comp   3.252200pF   3.221000pF   3.293600pF
[Temperature Range]   25.000000   0.140000k   -40.000000
[Pullup Reference]   3.300000V   2.700000V   3.600000V
[Pulldown Reference]   0.0V   0.0V   0.0V
[POWER Clamp Reference]   3.300000V   2.700000V   3.600000V
[GND Clamp Reference]   0.0V   0.0V   0.0V
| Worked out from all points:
|   slope of the pulldown table from 0 to 0.495 V, typ, clamps not added: 14 ohm
|   slope of the pullup table from 0 to 0.495 V, typ, clamps not added: 13.7 ohm
|   GND clamp passes 1 mA (typ) near -0.50 V on its own axis
|   POWER clamp passes 1 mA (typ) near -0.85 V on its own axis
|   rising waveform, R_fixture 50.000000, V_fixture 3.300000: 20-80 % time 246ps typ, 338ps min, 231ps max; typ from 0.764 V to 3.3 V
|   rising waveform, R_fixture 50.000000, V_fixture 0.0: 20-80 % time 3.15ns typ, 6.46ns min, 2.09ns max; typ from 0 V to 2.55 V
|   falling waveform, R_fixture 50.000000, V_fixture 3.300000: 20-80 % time 2.58ns typ, 5.69ns min, 1.62ns max; typ from 3.3 V to 0.764 V
|   falling waveform, R_fixture 50.000000, V_fixture 0.0: 20-80 % time 1ns typ, 1.54ns min, 764ps max; typ from 2.55 V to 0 V
[Pulldown]
|Voltage   I(typ)   I(min)   I(max)
-3.3V     -56.06mA   -29.42mA   -74.35mA
-900mV    -56.06mA   -29.42mA   -74.35mA
-700mV    -51.09mA   -29.42mA   -65.48mA
-500mV    -39.32mA   -24.2mA    -50.88mA
300mV     22.62mA    13.13mA    30.42mA
800mV     52.54mA    29.36mA    71.75mA
1.3V      72.91mA    38.82mA    101.4mA
1.8V      84.02mA    42.13mA    119.4mA
2.2V      86.43mA    42.46mA    124.5mA
5.5V      92.01mA    45.75mA    133mA
6.1V      98.6mA     49.6mA     142.1mA
6.6V      107.5mA    54.5mA     155mA
[Pullup]
|Voltage   I(typ)   I(min)   I(max)
-3.3V     62.6mA     35.14mA    84.13mA
-900mV    62.6mA     35.14mA    84.13mA
-800mV    62.12mA    35.14mA    79.56mA
-600mV    50.26mA    32.47mA    61.94mA
200mV     -15.65mA   -9.933mA   -19.95mA
700mV     -48.51mA   -30.11mA   -62.22mA
1.3V      -76.68mA   -45.83mA   -99.4mA
2V        -95.1mA    -53.38mA   -125.6mA
2.9V      -101.6mA   -55.08mA   -137mA
5.7V      -107mA     -58mA      -144mA
6.2V      -109mA     -61mA      -146mA
6.6V      -114mA     -67mA      -152mA
[GND_clamp]
|Voltage   I(typ)   I(min)   I(max)
-3.3V     -9.848A    -9.957A    -9.458A
-1.2V     -3.312A    -4.013A    -2.863A
-1.13V    -2.381A    -3.274A    -1.769A
-1.06V    -1.452A    -2.535A    -684.8mA
-990mV    -542.9mA   -1.798A    -88.04mA
-920mV    -87.13mA   -1.064A    -28.45mA
-850mV    -22.11mA   -382.4mA   -19.62mA
-780mV    -11.98mA   -86.98mA   -13.73mA
-710mV    -7.63mA    -22.27mA   -8.759mA
-640mV    -4.504mA   -7.781mA   -4.831mA
-360mV    -39.8uA    -178.9uA   -19.56uA
3.28V     83.52uA    56.87uA    102.4uA
[POWER_clamp]
|Voltage   I(typ)   I(min)   I(max)
-3.28V    1.355A     1.167A     1.664A
-1.16V    105.7mA    131.6mA    95.69mA
-1.12V    84.97mA    114mA      70.27mA
-1.08V    65.05mA    96.83mA    46.54mA
-1.04V    46.34mA    80.15mA    25.76mA
-1V       29.51mA    64.13mA    10.3mA
-960mV    15.69mA    48.99mA    2.571mA
-920mV    6.373mA    35.1mA     455.6uA
-840mV    490.7uA    13.24mA    11.36uA
-760mV    27.33uA    2.767mA    276.6nA
-640mV    346.6nA    134.1uA    15.48nA
0V        0A         19.91nA    0A
[Ramp]
| variable   typ   min   max
dV/dt_r  1.53198/3.14989n   1.08372/6.45647n   1.76610/2.08903n
dV/dt_f  1.52117/2.57663n   1.01748/5.68257n   1.77923/1.61559n
R_load = 50.000000
[Rising Waveform]
R_fixture= 50.000000
V_fixture= 3.300000
V_fixture_min= 2.700000
V_fixture_max= 3.600000
|time   V(typ)   V(min)   V(max)
0s        764mV      1.001V     633.8mV
1.065ns   763.9mV    1.001V     779.1mV
1.415ns   962.9mV    1.001V     3.102V
1.654ns   2.11V      998.6mV    3.532V
1.78ns    2.889V     1V         3.565V
1.948ns   3.196V     1.014V     3.579V
2.396ns   3.285V     1.27V      3.59V
2.775ns   3.289V     2.365V     3.594V
3.041ns   3.292V     2.639V     3.595V
6.979ns   3.299V     2.699V     3.599V
[Rising Waveform]
R_fixture= 50.000000
V_fixture= 0.0
V_fixture_min= 0.0
V_fixture_max= 0.0
|time   V(typ)   V(min)   V(max)
0s        35.18uV    27.89uV    37.97uV
1.441ns   -15.23mV   197.1uV    -23.32mV
2.432ns   92.1mV     -12.3mV    549.2mV
4.685ns   1.116V     105.3mV    2.421V
5.405ns   1.495V     194.8mV    2.659V
6.757ns   2.075V     409.5mV    2.816V
8.559ns   2.359V     738.2mV    2.894V
12.52ns   2.511V     1.399V     2.936V
16.31ns   2.542V     1.659V     2.942V
44.86ns   2.553V     1.806V     2.943V
[Falling Waveform]
R_fixture= 50.000000
V_fixture= 3.300000
V_fixture_min= 2.700000
V_fixture_max= 3.600000
|time   V(typ)   V(min)   V(max)
0s        3.299V     2.699V     3.599V
1.892ns   3.305V     2.705V     3.474V
2.703ns   3.156V     2.704V     2.475V
4.054ns   2.335V     2.675V     1.113V
4.595ns   2.011V     2.625V     879.2mV
5.766ns   1.335V     2.467V     745.9mV
7.838ns   945.5mV    2.083V     674mV
11.26ns   823.6mV    1.429V     643.5mV
14.5ns    789.1mV    1.198V     636.8mV
44.86ns   764mV      1.001V     633.8mV
[Falling Waveform]
R_fixture= 50.000000
V_fixture= 0.0
V_fixture_min= 0.0
V_fixture_max= 0.0
|time   V(typ)   V(min)   V(max)
0s        2.553V     1.806V     2.943V
560.6ps   2.506V     1.808V     2.854V
1.037ns   2.269V     1.748V     2.5V
1.345ns   1.97V      1.641V     1.892V
1.906ns   1.033V     1.29V      588.2mV
2.144ns   693.5mV    1.096V     187.1mV
2.298ns   502mV      973.8mV    54.13mV
2.887ns   44.18mV    558.6mV    2.273mV
3.924ns   1.643mV    97.83mV    696.2uV
6.979ns   35.18uV    27.89uV    37.97uV
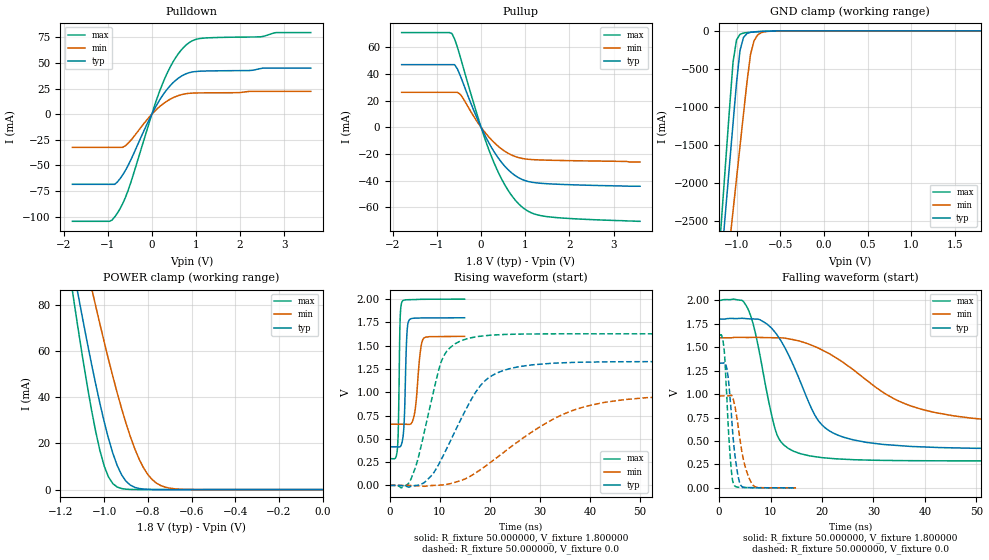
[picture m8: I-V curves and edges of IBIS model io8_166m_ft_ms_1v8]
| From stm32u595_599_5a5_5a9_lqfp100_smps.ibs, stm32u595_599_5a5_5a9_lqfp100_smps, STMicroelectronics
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|   Model io8_166m_ft_ms_1v8
[Model]  io8_166m_ft_ms_1v8
Model_type I/O
Polarity   Non-Inverting
Enable   Active-Low
Vinl =   0.540000V
Vinh =   1.260000V
Vmeas =  0.900000V
Cref =   50.000000pF
Rref =   100.000000M
Vref =   0.0V
C_comp   3.358200pF   3.352700pF   3.400300pF
[Temperature Range]   25.000000   0.140000k   -40.000000
[Pullup Reference]   1.800000V   1.600000V   2.000000V
[Pulldown Reference]   0.0V   0.0V   0.0V
[POWER Clamp Reference]   1.800000V   1.600000V   2.000000V
[GND Clamp Reference]   0.0V   0.0V   0.0V
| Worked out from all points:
|   slope of the pulldown table from 0 to 0.27 V, typ, clamps not added: 13.6 ohm
|   slope of the pullup table from 0 to 0.27 V, typ, clamps not added: 15.9 ohm
|   GND clamp passes 1 mA (typ) near -0.51 V on its own axis
|   POWER clamp passes 1 mA (typ) near -0.86 V on its own axis
|   rising waveform, R_fixture 50.000000, V_fixture 1.800000: 20-80 % time 446ps typ, 897ps min, 295ps max; typ from 0.414 V to 1.8 V
|   rising waveform, R_fixture 50.000000, V_fixture 0.0: 20-80 % time 7.83ns typ, 16.8ns min, 4.3ns max; typ from 0 V to 1.33 V
|   falling waveform, R_fixture 50.000000, V_fixture 1.800000: 20-80 % time 7.18ns typ, 16.9ns min, 3.85ns max; typ from 1.8 V to 0.414 V
|   falling waveform, R_fixture 50.000000, V_fixture 0.0: 20-80 % time 1.31ns typ, 1.89ns min, 978ps max; typ from 1.33 V to 0 V
[Pulldown]
|Voltage   I(typ)   I(min)   I(max)
-1.8V     -68.38mA   -32.32mA   -104.4mA
-960mV    -68.38mA   -32.32mA   -104.4mA
-780mV    -66.08mA   -32.32mA   -96.42mA
-660mV    -59.2mA    -32.31mA   -87.22mA
-540mV    -50.22mA   -28.51mA   -74.66mA
0V        0A         -200fA     0A
240mV     18.04mA    9.6mA      29.42mA
480mV     30.68mA    16.02mA    50.95mA
780mV     39.48mA    19.99mA    67.57mA
1.14V     41.99mA    20.78mA    74.01mA
2.82V     44.93mA    22.28mA    79.57mA
3.6V      44.93mA    22.28mA    79.57mA
[Pullup]
|Voltage   I(typ)   I(min)   I(max)
-1.8V     47.02mA    26.28mA    71.1mA
-660mV    47.02mA    26.28mA    70.37mA
-600mV    47.02mA    26.28mA    66.18mA
-480mV    39.45mA    25.02mA    53.78mA
-60mV     4.42mA     2.808mA    6.308mA
240mV     -15.38mA   -9.6mA     -22.37mA
420mV     -24.43mA   -15.12mA   -35.87mA
600mV     -31.41mA   -19.24mA   -46.67mA
960mV     -39.54mA   -23.52mA   -60.64mA
1.2V      -41.44mA   -24.28mA   -64.94mA
1.56V     -42.42mA   -24.69mA   -67.24mA
3.6V      -44.2mA    -26mA      -70.5mA
[GND_clamp]
|Voltage   I(typ)   I(min)   I(max)
-1.8V     -9.908A    -9.683A    -9.994A
-1.2V     -3.383A    -4.084A    -2.934A
-1.16V    -2.841A    -3.655A    -2.294A
-1.12V    -2.299A    -3.226A    -1.656A
-1.04V    -1.218A    -2.369A    -414.2mA
-1V       -684.7mA   -1.941A    -119.2mA
-960mV    -257.2mA   -1.514A    -45.66mA
-920mV    -87.03mA   -1.089A    -28.93mA
-840mV    -19.35mA   -312.8mA   -18.97mA
-800mV    -13.55mA   -132.4mA   -15.49mA
-720mV    -8.042mA   -25.67mA   -9.491mA
1.8V      0A         13.64nA    0A
[POWER_clamp]
|Voltage   I(typ)   I(min)   I(max)
-1.8V     470.8mA    433.7mA    554.6mA
-1.14V    95.25mA    122.7mA    82.82mA
-1.12V    84.97mA    114mA      70.27mA
-1.06V    55.51mA    88.42mA    35.67mA
-1.04V    46.34mA    80.15mA    25.76mA
-1V       29.51mA    64.13mA    10.3mA
-940mV    10.39mA    41.86mA    1.109mA
-900mV    3.624mA    28.77mA    182.8uA
-840mV    490.7uA    13.24mA    11.35uA
-800mV    116.8uA    6.532mA    1.77uA
-740mV    13.2uA     1.724mA    109.3nA
0V        0A         18.75nA    0A
[Ramp]
| variable   typ   min   max
dV/dt_r  0.79770/7.82234n   0.58781/16.72006n   0.97668/4.28748n
dV/dt_f  0.83162/7.15493n   0.56326/16.85217n   1.02770/3.84517n
R_load = 50.000000
[Rising Waveform]
R_fixture= 50.000000
V_fixture= 1.800000
V_fixture_min= 1.600000
V_fixture_max= 2.000000
|time   V(typ)   V(min)   V(max)
0s        413.9mV    656.8mV    287.2mV
1.532ns   413.5mV    656.9mV    391.6mV
1.742ns   412.7mV    656.9mV    686.4mV
2.072ns   415.2mV    656.9mV    1.778V
2.432ns   456.6mV    656.9mV    1.969V
3.423ns   1.62V      655.7mV    1.993V
3.844ns   1.773V     654.4mV    1.994V
4.985ns   1.796V     781.5mV    1.995V
6.637ns   1.798V     1.569V     1.998V
14.95ns   1.8V       1.6V       2V
[Rising Waveform]
R_fixture= 50.000000
V_fixture= 0.0
V_fixture_min= 0.0
V_fixture_max= 0.0
|time   V(typ)   V(min)   V(max)
0s        2.605uV    2.596uV    1.263uV
4.204ns   -11mV      -767.8uV   63.32mV
7.007ns   36mV       -9.68mV    598.5mV
10.41ns   290.6mV    4.55mV     1.344V
15.42ns   836.4mV    78.5mV     1.574V
18.62ns   1.102V     187.8mV    1.604V
22.62ns   1.232V     348.9mV    1.62V
33.43ns   1.314V     732.4mV    1.627V
42.64ns   1.326V     889mV      1.628V
99.7ns    1.33V      980.3mV    1.628V
[Falling Waveform]
R_fixture= 50.000000
V_fixture= 1.800000
V_fixture_min= 1.600000
V_fixture_max= 2.000000
|time   V(typ)   V(min)   V(max)
0s        1.8V       1.6V       2V
5.606ns   1.803V     1.603V     1.91V
7.007ns   1.8V       1.604V     1.663V
11.21ns   1.636V     1.6V       574mV
15.82ns   1.128V     1.562V     364.1mV
20.02ns   669.2mV    1.47V      322mV
28.63ns   485mV      1.149V     296.6mV
37.24ns   441.5mV    873.8mV    289.9mV
49.05ns   422.6mV    742.9mV    287.7mV
99.7ns    413.9mV    656.8mV    287.2mV
[Falling Waveform]
R_fixture= 50.000000
V_fixture= 0.0
V_fixture_min= 0.0
V_fixture_max= 0.0
|time   V(typ)   V(min)   V(max)
0s        1.33V      980.3mV    1.628V
900.9ps   1.331V     980.3mV    1.517V
1.141ns   1.335V     980.3mV    1.365V
1.532ns   1.266V     980.2mV    954.2mV
2.252ns   885.7mV    987.4mV    275.1mV
2.883ns   448.8mV    918.8mV    33.35mV
4.114ns   39.01mV    499.7mV    4.42mV
4.985ns   5.585mV    244.9mV    3.315mV
6.366ns   1.917mV    46.22mV    2.099mV
14.95ns   2.605uV    2.596uV    1.263uV
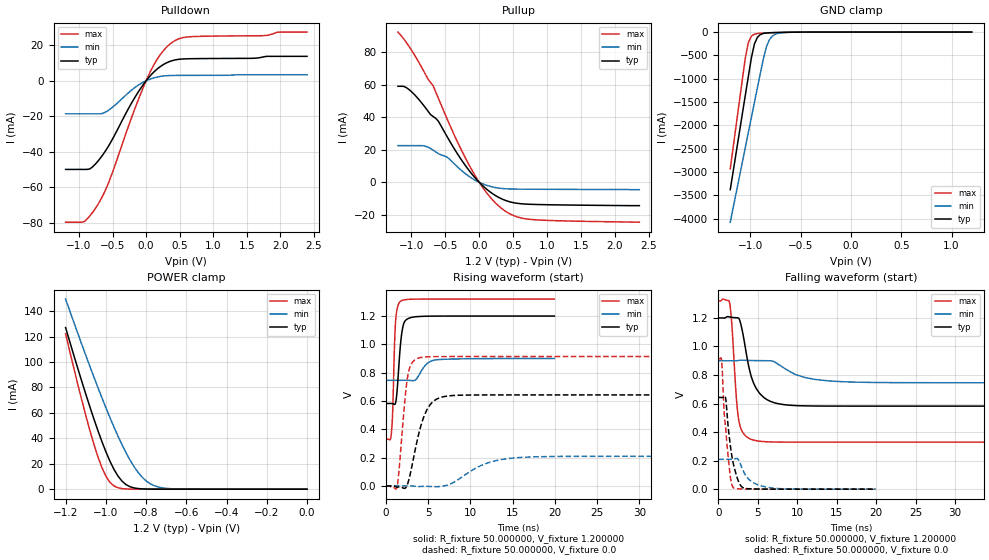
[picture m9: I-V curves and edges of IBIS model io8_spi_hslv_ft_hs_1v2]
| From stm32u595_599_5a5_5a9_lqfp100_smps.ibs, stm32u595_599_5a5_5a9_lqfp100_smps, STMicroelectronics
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|   Model io8_spi_hslv_ft_hs_1v2
[Model]  io8_spi_hslv_ft_hs_1v2
Model_type I/O
Polarity   Non-Inverting
Enable   Active-Low
Vinl =   0.360000V
Vinh =   0.840000V
Vmeas =  0.600000V
Cref =   50.000000pF
Rref =   100.000000M
Vref =   0.0V
C_comp   3.133100pF   3.070300pF   3.178200pF
[Temperature Range]   25.000000   0.140000k   -40.000000
[Pullup Reference]   1.200000V   0.900000V   1.320000V
[Pulldown Reference]   0.0V   0.0V   0.0V
[POWER Clamp Reference]   1.200000V   0.900000V   1.320000V
[GND Clamp Reference]   0.0V   0.0V   0.0V
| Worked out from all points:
|   slope of the pulldown table from 0 to 0.18 V, typ, clamps not added: 25.4 ohm
|   slope of the pullup table from 0 to 0.18 V, typ, clamps not added: 27.8 ohm
|   GND clamp passes 1 mA (typ) near -0.51 V on its own axis
|   POWER clamp passes 1 mA (typ) near -0.86 V on its own axis
|   rising waveform, R_fixture 50.000000, V_fixture 1.200000: 20-80 % time 504ps typ, 1.13ns min, 303ps max; typ from 0.582 V to 1.2 V
|   rising waveform, R_fixture 50.000000, V_fixture 0.0: 20-80 % time 1.63ns typ, 3.84ns min, 812ps max; typ from 0 V to 0.643 V
|   falling waveform, R_fixture 50.000000, V_fixture 1.200000: 20-80 % time 1.65ns typ, 3.76ns min, 725ps max; typ from 1.2 V to 0.582 V
|   falling waveform, R_fixture 50.000000, V_fixture 0.0: 20-80 % time 998ps typ, 1.69ns min, 751ps max; typ from 0.643 V to 0 V
[Pulldown]
|Voltage   I(typ)   I(min)   I(max)
-1.2V     -49.85mA   -18.57mA   -79.56mA
-920mV    -49.85mA   -18.57mA   -79.19mA
-840mV    -49.59mA   -18.57mA   -76.08mA
-720mV    -45.32mA   -18.57mA   -69.74mA
-560mV    -36.71mA   -16.58mA   -57.44mA
-200mV    -11.43mA   -4.74mA    -19.03mA
0V        0A         -500fA     0A
160mV     6.476mA    2.075mA    11.78mA
360mV     10.99mA    2.989mA    20.81mA
480mV     12.07mA    3.053mA    23.52mA
640mV     12.43mA    3.074mA    24.76mA
2.4V      13.78mA    3.432mA    27.43mA
[Pullup]
|Voltage   I(typ)   I(min)   I(max)
-1.2V     59.07mA    22.59mA    92.39mA
-1V       55.77mA    22.59mA    81.3mA
-800mV    46.21mA    22.35mA    66.86mA
-680mV    40.46mA    19.8mA     59.32mA
-600mV    37.35mA    17.55mA    51.35mA
-320mV    17.39mA    9.466mA    24.7mA
-80mV     3.667mA    1.75mA     5.47mA
120mV     -4.592mA   -1.936mA   -7.077mA
320mV     -9.941mA   -3.694mA   -15.71mA
520mV     -12.61mA   -4.111mA   -20.65mA
760mV     -13.48mA   -4.204mA   -22.78mA
2.36V     -14.3mA    -4.5mA     -24.47mA
[GND_clamp]
|Voltage   I(typ)   I(min)   I(max)
-1.2V     -3.379A    -4.076A    -2.932A
-1.05V    -1.35A     -2.47A     -550.7mA
-1.02V    -947.8mA   -2.149A    -221.5mA
-990mV    -552.4mA   -1.829A    -88.44mA
-960mV    -255.3mA   -1.51A     -44.87mA
-930mV    -111.8mA   -1.191A    -30.68mA
-870mV    -28.35mA   -564.6mA   -21.34mA
-840mV    -18.65mA   -309.5mA   -18.49mA
-810mV    -14.07mA   -161.6mA   -15.92mA
-780mV    -11.37mA   -83.33mA   -13.53mA
-600mV    -3.009mA   -4.321mA   -3.091mA
1.2V      0A         13.65nA    0A
[POWER_clamp]
|Voltage   I(typ)   I(min)   I(max)
-1.2V     127mA      149.4mA    122.2mA
-1.12V    84.97mA    114mA      70.27mA
-1.06V    55.51mA    88.42mA    35.67mA
-1.02V    37.63mA    72.04mA    17.17mA
-1V       29.51mA    64.13mA    10.3mA
-960mV    15.69mA    48.99mA    2.571mA
-900mV    3.624mA    28.77mA    182.8uA
-840mV    490.7uA    13.24mA    11.35uA
-800mV    116.8uA    6.532mA    1.77uA
-740mV    13.2uA     1.723mA    109.1nA
-620mV    167.4nA    79.36uA    0A
0V        0A         17.87nA    0A
[Ramp]
| variable   typ   min   max
dV/dt_r  0.38564/1.63136n   0.12554/3.83243n   0.54825/0.80766n
dV/dt_f  0.37079/1.64428n   92.44800m/3.75443n  0.59435/0.72074n
R_load = 50.000000
[Rising Waveform]
R_fixture= 50.000000
V_fixture= 1.200000
V_fixture_min= 0.900000
V_fixture_max= 1.320000
|time   V(typ)   V(min)   V(max)
0s        582.1mV    746mV      329.5mV
640.6ps   582.4mV    746mV      363.2mV
800.8ps   581.1mV    746mV      515.5mV
1.041ns   575.3mV    746mV      1.026V
1.161ns   589mV      746mV      1.171V
1.722ns   992.8mV    746mV      1.304V
2.162ns   1.154V     746.1mV    1.314V
3.083ns   1.191V     744mV      1.319V
5.886ns   1.2V       890.4mV    1.32V
19.94ns   1.2V       900mV      1.32V
[Rising Waveform]
R_fixture= 50.000000
V_fixture= 0.0
V_fixture_min= 0.0
V_fixture_max= 0.0
|time   V(typ)   V(min)   V(max)
0s        -2.993uV   845.8nV    -21.62uV
1.301ns   -8.521mV   -7.394uV   -14.91mV
2.302ns   -15.91mV   34.86uV    636.8mV
2.603ns   18.64mV    136.9uV    780.9mV
3.804ns   345.9mV    -4.871mV   901.9mV
5.205ns   570.8mV    -4.056mV   912.4mV
7.407ns   635.7mV    8.283mV    913.6mV
11.51ns   642.5mV    150.1mV    913.8mV
15.72ns   642.7mV    200.1mV    913.8mV
49.85ns   642.8mV    209.3mV    913.9mV
[Falling Waveform]
R_fixture= 50.000000
V_fixture= 1.200000
V_fixture_min= 0.900000
V_fixture_max= 1.320000
|time   V(typ)   V(min)   V(max)
0s        1.2V       900mV      1.32V
1.401ns   1.208V     900mV      1.316V
1.702ns   1.205V     900mV      1.174V
2.302ns   1.202V     899.9mV    638.7mV
2.603ns   1.198V     902.6mV    484.4mV
4.204ns   786.2mV    901.8mV    348.8mV
5.806ns   641.2mV    900.6mV    333.3mV
8.909ns   589.1mV    829.8mV    329.7mV
17.02ns   582.1mV    750.7mV    329.5mV
49.85ns   582.1mV    746mV      329.5mV
[Falling Waveform]
R_fixture= 50.000000
V_fixture= 0.0
V_fixture_min= 0.0
V_fixture_max= 0.0
|time   V(typ)   V(min)   V(max)
0s        642.8mV    209.3mV    913.9mV
440.4ps   642.7mV    209.3mV    895.5mV
720.7ps   647.3mV    209.4mV    572.5mV
920.9ps   644.9mV    209.4mV    443.5mV
1.522ns   313.1mV    209.2mV    94.31mV
1.922ns   177.2mV    210.3mV    10.48mV
2.643ns   44.96mV    198.4mV    2.317mV
3.403ns   5.217mV    103.1mV    891.1uV
6.887ns   266.5uV    7.442mV    25.61uV
19.94ns   -2.993uV   845.8nV    -21.62uV
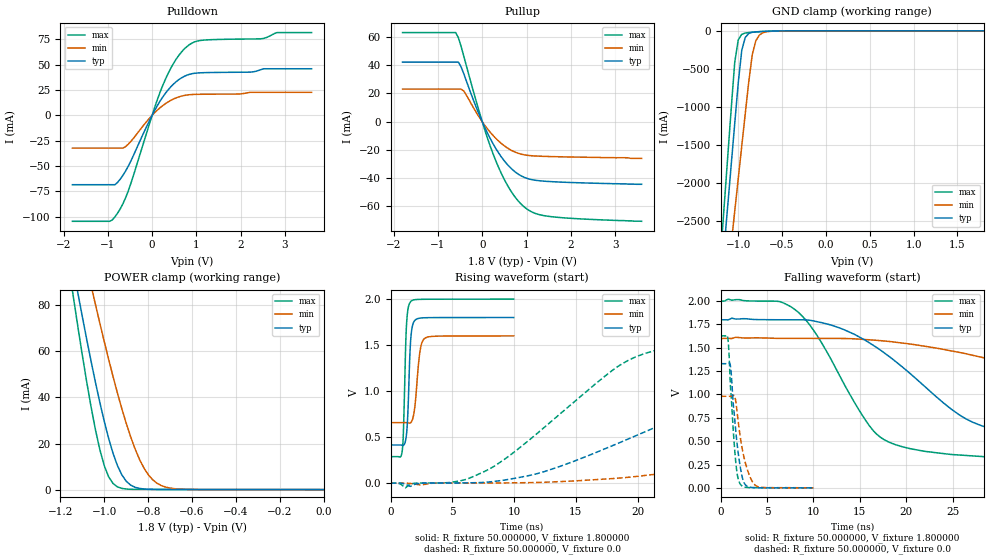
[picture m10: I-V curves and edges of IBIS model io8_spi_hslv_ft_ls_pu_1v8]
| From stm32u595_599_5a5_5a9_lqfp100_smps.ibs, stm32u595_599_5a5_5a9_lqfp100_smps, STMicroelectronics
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|   Model io8_spi_hslv_ft_ls_pu_1v8
[Model]  io8_spi_hslv_ft_ls_pu_1v8
Model_type I/O
Polarity   Non-Inverting
Enable   Active-Low
Vinl =   0.540000V
Vinh =   1.260000V
Vmeas =  0.900000V
Cref =   50.000000pF
Rref =   100.000000M
Vref =   0.0V
C_comp   3.338700pF   3.332500pF   3.379000pF
[Temperature Range]   25.000000   0.140000k   -40.000000
[Pullup Reference]   1.800000V   1.600000V   2.000000V
[Pulldown Reference]   0.0V   0.0V   0.0V
[POWER Clamp Reference]   1.800000V   1.600000V   2.000000V
[GND Clamp Reference]   0.0V   0.0V   0.0V
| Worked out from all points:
|   slope of the pulldown table from 0 to 0.27 V, typ, clamps not added: 13.6 ohm
|   slope of the pullup table from 0 to 0.27 V, typ, clamps not added: 15.9 ohm
|   GND clamp passes 1 mA (typ) near -0.51 V on its own axis
|   POWER clamp passes 1 mA (typ) near -0.86 V on its own axis
|   rising waveform, R_fixture 50.000000, V_fixture 1.800000: 20-80 % time 238ps typ, 381ps min, 211ps max; typ from 0.414 V to 1.8 V
|   rising waveform, R_fixture 50.000000, V_fixture 0.0: 20-80 % time 15.3ns typ, 31.7ns min, 8.93ns max; typ from 0 V to 1.33 V
|   falling waveform, R_fixture 50.000000, V_fixture 1.800000: 20-80 % time 10.9ns typ, 26.5ns min, 6.09ns max; typ from 1.8 V to 0.414 V
|   falling waveform, R_fixture 50.000000, V_fixture 0.0: 20-80 % time 797ps typ, 1.07ns min, 621ps max; typ from 1.33 V to 0 V
[Pulldown]
|Voltage   I(typ)   I(min)   I(max)
-1.8V     -68.38mA   -32.32mA   -104.4mA
-960mV    -68.38mA   -32.32mA   -104.4mA
-780mV    -66.07mA   -32.32mA   -96.42mA
-540mV    -50.22mA   -28.51mA   -74.66mA
0V        0A         0A         0A
240mV     18.04mA    9.598mA    29.41mA
480mV     30.68mA    16.02mA    50.95mA
780mV     39.47mA    19.98mA    67.56mA
1.14V     41.98mA    20.77mA    74.01mA
2.46V     45.09mA    22.68mA    75.44mA
2.82V     45.89mA    22.68mA    81.56mA
3.6V      45.89mA    22.68mA    81.56mA
[Pullup]
|Voltage   I(typ)   I(min)   I(max)
-1.8V     42.2mA     23.08mA    63.09mA
-600mV    42.2mA     23.08mA    63.09mA
-540mV    42.2mA     23.08mA    59.56mA
-420mV    34.21mA    21.83mA    46.75mA
0V        630fA      250pA      0A
300mV     -18.63mA   -11.6mA    -27.18mA
600mV     -31.41mA   -19.24mA   -46.67mA
780mV     -36.41mA   -22mA      -54.88mA
960mV     -39.54mA   -23.51mA   -60.64mA
1.2V      -41.44mA   -24.28mA   -64.93mA
1.56V     -42.42mA   -24.69mA   -67.24mA
3.6V      -44.3mA    -26mA      -70.5mA
[GND_clamp]
|Voltage   I(typ)   I(min)   I(max)
-1.8V     -9.908A    -9.683A    -9.994A
-1.2V     -3.383A    -4.084A    -2.934A
-1.16V    -2.841A    -3.655A    -2.294A
-1.12V    -2.299A    -3.226A    -1.656A
-1.04V    -1.218A    -2.369A    -414.2mA
-1V       -684.7mA   -1.941A    -119.2mA
-960mV    -257.2mA   -1.514A    -45.66mA
-920mV    -87.03mA   -1.089A    -28.93mA
-840mV    -19.35mA   -312.8mA   -18.96mA
-800mV    -13.55mA   -132.4mA   -15.49mA
-720mV    -8.042mA   -25.66mA   -9.49mA
1.8V      0A         13.64nA    0A
[POWER_clamp]
|Voltage   I(typ)   I(min)   I(max)
-1.8V     470.9mA    433.7mA    554.6mA
-1.14V    95.28mA    122.7mA    82.88mA
-1.12V    85mA       114mA      70.34mA
-1.06V    55.55mA    88.43mA    35.73mA
-1.04V    46.38mA    80.17mA    25.83mA
-1V       29.54mA    64.14mA    10.37mA
-940mV    10.43mA    41.88mA    1.177mA
-900mV    3.66mA     28.79mA    250.5uA
-840mV    527.2uA    13.26mA    95.94uA
-800mV    154uA      6.55mA     88.41uA
-740mV    59.83uA    1.741mA    70.38uA
0V        0A         18.18nA    0A
[Ramp]
| variable   typ   min   max
dV/dt_r  0.79756/15.30003n   0.58795/31.69182n   0.97651/8.91745n
dV/dt_f  0.83132/10.91823n   0.56500/26.53402n   1.02742/6.07565n
R_load = 50.000000
[Rising Waveform]
R_fixture= 50.000000
V_fixture= 1.800000
V_fixture_min= 1.600000
V_fixture_max= 2.000000
|time   V(typ)   V(min)   V(max)
0s        414.5mV    657.6mV    287.6mV
940.9ps   412mV      657.7mV    348.6mV
1.041ns   411.3mV    657.7mV    561.7mV
1.281ns   523.2mV    657.2mV    1.697V
1.401ns   767.4mV    655.2mV    1.885V
1.622ns   1.542V     656mV      1.972V
1.962ns   1.768V     827.5mV    1.994V
2.402ns   1.794V     1.449V     1.998V
2.763ns   1.797V     1.573V     1.998V
9.97ns    1.8V       1.6V       2V
[Rising Waveform]
R_fixture= 50.000000
V_fixture= 0.0
V_fixture_min= 0.0
V_fixture_max= 0.0
|time   V(typ)   V(min)   V(max)
0s        425uV      507.6uV    388.2uV
6.006ns   2.436mV    1.278mV    36.58mV
11.61ns   94.26mV    6.724mV    511.2mV
19.62ns   501.4mV    68.52mV    1.359V
28.43ns   974.7mV    233.5mV    1.567V
34.03ns   1.155V     353.5mV    1.599V
43.24ns   1.262V     544.2mV    1.62V
59.26ns   1.313V     794.5mV    1.627V
77.28ns   1.327V     913.3mV    1.628V
199.4ns   1.33V      980.6mV    1.628V
[Falling Waveform]
R_fixture= 50.000000
V_fixture= 1.800000
V_fixture_min= 1.600000
V_fixture_max= 2.000000
|time   V(typ)   V(min)   V(max)
0s        1.8V       1.6V       2V
7.608ns   1.8V       1.6V       1.937V
10.01ns   1.787V     1.6V       1.687V
16.82ns   1.502V     1.58V      574mV
24.82ns   845mV      1.467V     358mV
28.43ns   655.1mV    1.391V     334mV
34.83ns   537.1mV    1.226V     311.1mV
48.45ns   459.6mV    911.8mV    294.1mV
64.06ns   431.1mV    773.1mV    289.1mV
199.4ns   414.5mV    657.6mV    287.6mV
[Falling Waveform]
R_fixture= 50.000000
V_fixture= 0.0
V_fixture_min= 0.0
V_fixture_max= 0.0
|time   V(typ)   V(min)   V(max)
0s        1.33V      980.6mV    1.628V
760.8ps   1.33V      980.7mV    1.607V
880.9ps   1.335V     980.8mV    1.466V
1.081ns   1.28V      980.6mV    1.04V
1.542ns   702.1mV    970.3mV    366.8mV
1.782ns   459.4mV    799.9mV    147.4mV
2.082ns   239.8mV    564.7mV    45.03mV
2.623ns   37.46mV    281.6mV    8.091mV
3.824ns   1.734mV    20.86mV    2.258mV
9.97ns    425uV      507.6uV    388.2uV
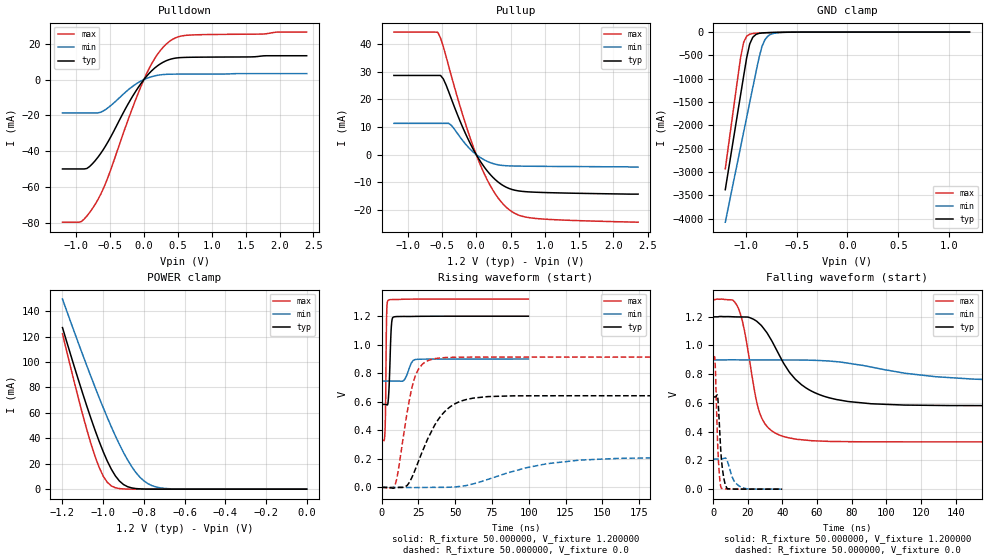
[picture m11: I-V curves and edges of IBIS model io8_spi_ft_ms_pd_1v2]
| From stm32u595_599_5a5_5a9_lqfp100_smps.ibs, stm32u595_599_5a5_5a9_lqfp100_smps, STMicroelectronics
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|   Model io8_spi_ft_ms_pd_1v2
[Model]  io8_spi_ft_ms_pd_1v2
Model_type I/O
Polarity   Non-Inverting
Enable   Active-Low
Vinl =   0.360000V
Vinh =   0.840000V
Vmeas =  0.600000V
Cref =   50.000000pF
Rref =   100.000000M
Vref =   0.0V
C_comp   3.132800pF   3.069700pF   3.178000pF
[Temperature Range]   25.000000   0.140000k   -40.000000
[Pullup Reference]   1.200000V   0.900000V   1.320000V
[Pulldown Reference]   0.0V   0.0V   0.0V
[POWER Clamp Reference]   1.200000V   0.900000V   1.320000V
[GND Clamp Reference]   0.0V   0.0V   0.0V
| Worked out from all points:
|   slope of the pulldown table from 0 to 0.18 V, typ, clamps not added: 25.4 ohm
|   slope of the pullup table from 0 to 0.18 V, typ, clamps not added: 27.8 ohm
|   GND clamp passes 1 mA (typ) near -0.51 V on its own axis
|   POWER clamp passes 1 mA (typ) near -0.86 V on its own axis
|   rising waveform, R_fixture 50.000000, V_fixture 1.200000: 20-80 % time 1.26ns typ, 3.37ns min, 606ps max; typ from 0.581 V to 1.2 V
|   rising waveform, R_fixture 50.000000, V_fixture 0.0: 20-80 % time 18.4ns typ, 45.6ns min, 9.09ns max; typ from 0 V to 0.642 V
|   falling waveform, R_fixture 50.000000, V_fixture 1.200000: 20-80 % time 21.9ns typ, 54.7ns min, 9.21ns max; typ from 1.2 V to 0.581 V
|   falling waveform, R_fixture 50.000000, V_fixture 0.0: 20-80 % time 2.2ns typ, 4.2ns min, 1.58ns max; typ from 0.642 V to 0 V
[Pulldown]
|Voltage   I(typ)   I(min)   I(max)
-1.2V     -49.85mA   -18.57mA   -79.56mA
-920mV    -49.85mA   -18.57mA   -79.19mA
-840mV    -49.59mA   -18.57mA   -76.08mA
-720mV    -45.32mA   -18.57mA   -69.74mA
-560mV    -36.71mA   -16.58mA   -57.44mA
-200mV    -11.43mA   -4.74mA    -19.03mA
0V        -10fA      -600fA     0A
160mV     6.476mA    2.075mA    11.78mA
360mV     10.99mA    2.989mA    20.81mA
480mV     12.07mA    3.053mA    23.52mA
640mV     12.42mA    3.074mA    24.76mA
2.4V      13.31mA    3.34mA     26.51mA
[Pullup]
|Voltage   I(typ)   I(min)   I(max)
-1.2V     28.65mA    11.31mA    44.34mA
-560mV    28.65mA    11.31mA    44.25mA
-480mV    27.42mA    11.31mA    39.11mA
-360mV    20.01mA    10.55mA    28.26mA
-160mV    7.809mA    3.931mA    11.44mA
40mV      -1.648mA   -721.3uA   -2.521mA
240mV     -8.14mA    -3.2mA     -12.72mA
360mV     -10.68mA   -3.85mA    -16.99mA
480mV     -12.27mA   -4.078mA   -19.94mA
640mV     -13.22mA   -4.169mA   -22.09mA
880mV     -13.63mA   -4.232mA   -23.14mA
2.36V     -14.3mA    -4.5mA     -24.46mA
[GND_clamp]
|Voltage   I(typ)   I(min)   I(max)
-1.2V     -3.379A    -4.076A    -2.932A
-1.05V    -1.35A     -2.47A     -550.7mA
-1.02V    -947.8mA   -2.15A     -221.5mA
-990mV    -552.4mA   -1.829A    -88.45mA
-960mV    -255.3mA   -1.51A     -44.89mA
-930mV    -111.8mA   -1.191A    -30.69mA
-870mV    -28.36mA   -564.6mA   -21.36mA
-840mV    -18.66mA   -309.5mA   -18.51mA
-810mV    -14.08mA   -161.6mA   -15.94mA
-780mV    -11.38mA   -83.33mA   -13.55mA
-600mV    -3.019mA   -4.329mA   -3.104mA
1.2V      30.28uA    18.17uA    37.27uA
[POWER_clamp]
|Voltage   I(typ)   I(min)   I(max)
-1.2V     127mA      149.4mA    122.2mA
-1.12V    84.97mA    114mA      70.27mA
-1.06V    55.51mA    88.42mA    35.67mA
-1.02V    37.63mA    72.04mA    17.17mA
-1V       29.51mA    64.13mA    10.3mA
-960mV    15.69mA    48.99mA    2.571mA
-900mV    3.624mA    28.77mA    182.8uA
-840mV    490.7uA    13.24mA    11.35uA
-800mV    116.8uA    6.532mA    1.77uA
-740mV    13.2uA     1.724mA    109.1nA
-620mV    167.4nA    79.36uA    0A
0V        0A         17.87nA    0A
[Ramp]
| variable   typ   min   max
dV/dt_r  0.38525/18.34983n   0.12538/45.50853n   0.54788/9.06810n
dV/dt_f  0.37090/21.84967n   92.41800m/54.74519n 0.59418/9.20100n
R_load = 50.000000
[Rising Waveform]
R_fixture= 50.000000
V_fixture= 1.200000
V_fixture_min= 0.900000
V_fixture_max= 1.320000
|time   V(typ)   V(min)   V(max)
0s        581.3mV    745.2mV    329.2mV
2.202ns   581.5mV    745.2mV    378.8mV
2.603ns   581.3mV    745.2mV    523.7mV
3.403ns   578.7mV    745.2mV    1.224V
4.404ns   602.8mV    745.2mV    1.311V
6.406ns   1.1V       745.2mV    1.316V
7.808ns   1.192V     745.2mV    1.316V
15.02ns   1.198V     749.3mV    1.318V
22.82ns   1.198V     895.9mV    1.319V
99.7ns    1.2V       899.5mV    1.319V
[Rising Waveform]
R_fixture= 50.000000
V_fixture= 0.0
V_fixture_min= 0.0
V_fixture_max= 0.0
|time   V(typ)   V(min)   V(max)
0s        1.399uV    1.111uV    1.278uV
9.009ns   -2.649mV   -415.1nV   15.29mV
16.82ns   10.1mV     -845.8uV   494.1mV
21.62ns   95.17mV    -1.412mV   741.6mV
25.23ns   188.6mV    -1.081mV   832mV
33.03ns   375.6mV    -43.31uV   893.9mV
48.05ns   575mV      2.188mV    911.3mV
72.07ns   636.1mV    55.58mV    912.8mV
134.5ns   642mV      191.1mV    912.9mV
299.1ns   642.1mV    209.1mV    912.9mV
[Falling Waveform]
R_fixture= 50.000000
V_fixture= 1.200000
V_fixture_min= 0.900000
V_fixture_max= 1.320000
|time   V(typ)   V(min)   V(max)
0s        1.2V       899.5mV    1.319V
13.81ns   1.199V     900mV      1.279V
18.02ns   1.198V     899.8mV    1.109V
24.02ns   1.177V     899.7mV    676.9mV
27.03ns   1.149V     899.6mV    526.4mV
40.84ns   873.8mV    899.1mV    365.9mV
58.26ns   673.8mV    896.8mV    336.6mV
91.29ns   594.4mV    849.8mV    329.6mV
150.2ns   581.7mV    766mV      329.2mV
299.1ns   581.3mV    745.2mV    329.2mV
[Falling Waveform]
R_fixture= 50.000000
V_fixture= 0.0
V_fixture_min= 0.0
V_fixture_max= 0.0
|time   V(typ)   V(min)   V(max)
0s        642.1mV    209.1mV    912.9mV
1.201ns   641.6mV    209.1mV    872.3mV
2.643ns   644.3mV    209.1mV    313.7mV
3.684ns   439.1mV    208.9mV    95.53mV
4.725ns   221.6mV    209mV      8.743mV
6.246ns   73.39mV    214.6mV    2.397mV
8.088ns   4.748mV    200.3mV    1.16mV
11.85ns   790.4uV    63.38mV    944.5uV
16.66ns   342.5uV    11.37mV    543.9uV
39.88ns   1.399uV    1.111uV    1.278uV
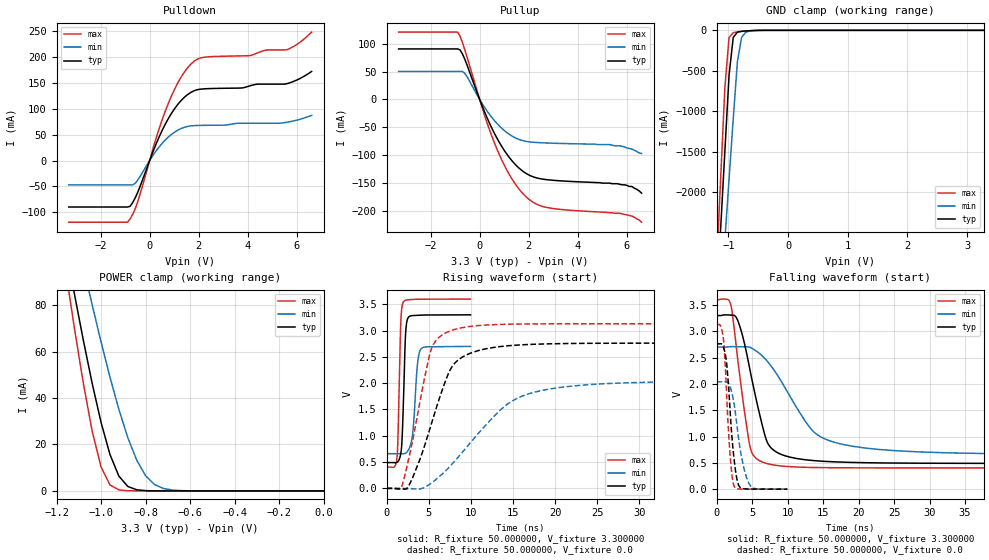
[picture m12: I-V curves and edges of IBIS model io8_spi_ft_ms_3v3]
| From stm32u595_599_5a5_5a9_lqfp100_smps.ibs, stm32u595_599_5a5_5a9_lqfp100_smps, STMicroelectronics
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|   Model io8_spi_ft_ms_3v3
[Model]  io8_spi_ft_ms_3v3
Model_type I/O
Polarity   Non-Inverting
Enable   Active-Low
Vinl =   0.990000V
Vinh =   2.310000V
Vmeas =  1.650000V
Cref =   50.000000pF
Rref =   100.000000M
Vref =   0.0V
C_comp   3.495300pF   3.468500pF   3.534700pF
[Temperature Range]   25.000000   0.140000k   -40.000000
[Pullup Reference]   3.300000V   2.700000V   3.600000V
[Pulldown Reference]   0.0V   0.0V   0.0V
[POWER Clamp Reference]   3.300000V   2.700000V   3.600000V
[GND Clamp Reference]   0.0V   0.0V   0.0V
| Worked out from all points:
|   slope of the pulldown table from 0 to 0.495 V, typ, clamps not added: 8.73 ohm
|   slope of the pullup table from 0 to 0.495 V, typ, clamps not added: 9.64 ohm
|   GND clamp passes 1 mA (typ) near -0.50 V on its own axis
|   POWER clamp passes 1 mA (typ) near -0.85 V on its own axis
|   rising waveform, R_fixture 50.000000, V_fixture 3.300000: 20-80 % time 328ps typ, 511ps min, 284ps max; typ from 0.49 V to 3.3 V
|   rising waveform, R_fixture 50.000000, V_fixture 0.0: 20-80 % time 3.45ns typ, 7.17ns min, 2.35ns max; typ from 0 V to 2.76 V
|   falling waveform, R_fixture 50.000000, V_fixture 3.300000: 20-80 % time 2.77ns typ, 5.94ns min, 1.85ns max; typ from 3.3 V to 0.49 V
|   falling waveform, R_fixture 50.000000, V_fixture 0.0: 20-80 % time 943ps typ, 1.38ns min, 766ps max; typ from 2.76 V to 0 V
[Pulldown]
|Voltage   I(typ)   I(min)   I(max)
-3.3V     -89.71mA   -47.06mA   -119mA
-900mV    -89.71mA   -47.06mA   -119mA
-700mV    -81.75mA   -47.06mA   -104.8mA
-500mV    -62.92mA   -38.71mA   -81.44mA
300mV     36.2mA     21.01mA    48.7mA
800mV     84.06mA    46.96mA    114.8mA
1.3V      116.7mA    62.08mA    162.3mA
1.8V      134.4mA    67.38mA    191.2mA
2.2V      138.3mA    67.91mA    199.2mA
4.1V      144.4mA    71.97mA    202.7mA
5.6V      148.4mA    73.95mA    213.9mA
6.6V      171.9mA    87.1mA     247.9mA
[Pullup]
|Voltage   I(typ)   I(min)   I(max)
-3.3V     90.49mA    50.18mA    120.6mA
-900mV    90.49mA    50.18mA    120.6mA
-800mV    88.72mA    50.18mA    113.4mA
-600mV    71.5mA     46.18mA    88.11mA
200mV     -22.26mA   -14.13mA   -28.39mA
700mV     -69mA      -42.82mA   -88.5mA
1.3V      -109.1mA   -65.19mA   -141.4mA
2V        -135.3mA   -75.91mA   -178.7mA
2.9V      -144.6mA   -78.33mA   -194.9mA
5.3V      -150mA     -81mA      -203mA
6.2V      -156mA     -89mA      -209mA
6.6V      -168mA     -97mA      -220mA
[GND_clamp]
|Voltage   I(typ)   I(min)   I(max)
-3.3V     -9.098A    -9.372A    -9.671A
-1.2V     -3.386A    -4.091A    -2.933A
-1.13V    -2.437A    -3.34A     -1.815A
-1.06V    -1.49A     -2.588A    -705.6mA
-990mV    -555.7mA   -1.839A    -89.03mA
-920mV    -88.12mA   -1.093A    -28.78mA
-850mV    -22.35mA   -387.4mA   -19.84mA
-780mV    -12.12mA   -88mA      -13.87mA
-710mV    -7.709mA   -22.52mA   -8.846mA
-640mV    -4.545mA   -7.864mA   -4.87mA
-360mV    -31.12uA   -173.5uA   -8.496uA
3.28V     0A         14.15nA    -7.901nA
[POWER_clamp]
|Voltage   I(typ)   I(min)   I(max)
-3.28V    1.355A     1.167A     1.664A
-1.16V    105.7mA    131.6mA    95.69mA
-1.12V    84.97mA    114mA      70.27mA
-1.08V    65.05mA    96.83mA    46.54mA
-1.04V    46.34mA    80.15mA    25.76mA
-1V       29.51mA    64.13mA    10.3mA
-960mV    15.69mA    48.99mA    2.571mA
-920mV    6.373mA    35.1mA     455.6uA
-840mV    490.7uA    13.24mA    11.36uA
-760mV    27.33uA    2.767mA    279.3nA
-640mV    348nA      134.1uA    17.45nA
0V        0A         19.95nA    0A
[Ramp]
| variable   typ   min   max
dV/dt_r  1.65714/3.44751n   1.22448/7.15313n   1.87854/2.34293n
dV/dt_f  1.68605/2.76557n   1.22282/5.92868n   1.91788/1.84403n
R_load = 50.000000
[Rising Waveform]
R_fixture= 50.000000
V_fixture= 3.300000
V_fixture_min= 2.700000
V_fixture_max= 3.600000
|time   V(typ)   V(min)   V(max)
0s        489.9mV    659.8mV    403.5mV
1.241ns   493.8mV    659.8mV    582.9mV
1.682ns   654.9mV    659.4mV    3.106V
1.982ns   1.537V     658.4mV    3.54V
2.262ns   2.939V     669.2mV    3.577V
2.603ns   3.254V     730.1mV    3.585V
3.083ns   3.285V     1.011V     3.593V
3.644ns   3.291V     2.313V     3.596V
4.024ns   3.293V     2.637V     3.597V
9.97ns    3.3V       2.7V       3.6V
[Rising Waveform]
R_fixture= 50.000000
V_fixture= 0.0
V_fixture_min= 0.0
V_fixture_max= 0.0
|time   V(typ)   V(min)   V(max)
0s        5.336uV    5.691uV    3.579uV
1.682ns   -10.94mV   162.2uV    -3.323mV
2.643ns   51.76mV    -7.562mV   572.3mV
5.285ns   1.206V     96.34mV    2.636V
6.246ns   1.697V     223.2mV    2.874V
7.928ns   2.348V     489.2mV    3.014V
10.33ns   2.592V     939.9mV    3.087V
14.17ns   2.708V     1.58V      3.12V
19.22ns   2.748V     1.886V     3.129V
59.82ns   2.762V     2.041V     3.131V
[Falling Waveform]
R_fixture= 50.000000
V_fixture= 3.300000
V_fixture_min= 2.700000
V_fixture_max= 3.600000
|time   V(typ)   V(min)   V(max)
0s        3.3V       2.7V       3.6V
1.922ns   3.31V      2.709V     3.544V
3.003ns   3.204V     2.708V     2.448V
4.805ns   2.202V     2.691V     757.1mV
6.486ns   1.191V     2.527V     514.7mV
7.327ns   846.3mV    2.401V     479.6mV
8.889ns   673.8mV    2.099V     444.4mV
13.57ns   544.5mV    1.105V     412.3mV
17.18ns   516.6mV    870mV      406.8mV
59.82ns   489.9mV    659.8mV    403.5mV
[Falling Waveform]
R_fixture= 50.000000
V_fixture= 0.0
V_fixture_min= 0.0
V_fixture_max= 0.0
|time   V(typ)   V(min)   V(max)
0s        2.762V     2.041V     3.131V
560.6ps   2.765V     2.041V     3.101V
981ps     2.697V     2.041V     2.843V
1.401ns   2.415V     2.044V     1.863V
1.862ns   1.602V     1.963V     740.7mV
2.482ns   556.7mV    1.618V     55.9mV
3.183ns   57.42mV    893.1mV    3.789mV
3.864ns   6.948mV    396.1mV    1.73mV
4.705ns   2.475mV    77.1mV     959.4uV
9.97ns    5.336uV    5.691uV    3.579uV
